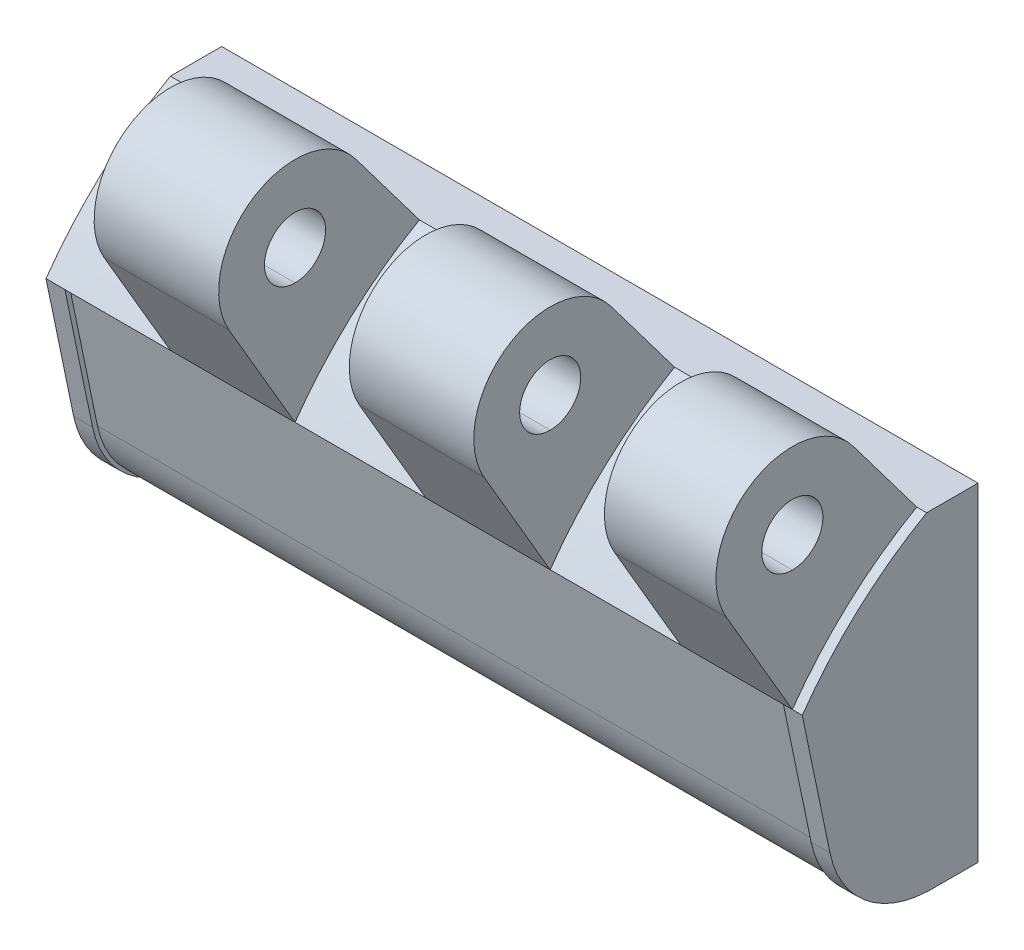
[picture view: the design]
ISO-10303-21;
HEADER;
FILE_DESCRIPTION(('STEP AP214'),'2;1');
FILE_NAME('part.step','',(''),(''),'','','');
FILE_SCHEMA(('AUTOMOTIVE_DESIGN { 1 0 10303 214 1 1 1 1 }'));
ENDSEC;
DATA;
#1=APPLICATION_CONTEXT('core data for automotive mechanical design processes');
#2=APPLICATION_PROTOCOL_DEFINITION('international standard','automotive_design',2000,#1);
#3=PRODUCT_CONTEXT('',#1,'mechanical');
#4=PRODUCT('Part','Part','',(#3));
#5=PRODUCT_RELATED_PRODUCT_CATEGORY('part','',(#4));
#6=PRODUCT_DEFINITION_FORMATION('','',#4);
#7=PRODUCT_DEFINITION_CONTEXT('part definition',#1,'design');
#8=PRODUCT_DEFINITION('design','',#6,#7);
#9=PRODUCT_DEFINITION_SHAPE('','',#8);
#10=(LENGTH_UNIT() NAMED_UNIT(*) SI_UNIT(.MILLI.,.METRE.));
#11=(NAMED_UNIT(*) PLANE_ANGLE_UNIT() SI_UNIT($,.RADIAN.));
#12=(NAMED_UNIT(*) SI_UNIT($,.STERADIAN.) SOLID_ANGLE_UNIT());
#13=UNCERTAINTY_MEASURE_WITH_UNIT(LENGTH_MEASURE(1.E-05),#10,'distance_accuracy_value','');
#14=(GEOMETRIC_REPRESENTATION_CONTEXT(3) GLOBAL_UNCERTAINTY_ASSIGNED_CONTEXT((#13)) GLOBAL_UNIT_ASSIGNED_CONTEXT((#10,
#11,#12)) REPRESENTATION_CONTEXT('',''));
#15=CARTESIAN_POINT('',(0.,0.,0.));
#16=DIRECTION('',(0.,0.,1.));
#17=DIRECTION('',(1.,0.,0.));
#18=AXIS2_PLACEMENT_3D('',#15,#16,#17);
#19=CARTESIAN_POINT('',(38.63875,-2.8772598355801,8.51410225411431));
#20=DIRECTION('',(0.,0.203476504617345,-0.979079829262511));
#21=DIRECTION('',(0.,-0.979079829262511,-0.203476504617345));
#22=AXIS2_PLACEMENT_3D('',#19,#20,#21);
#23=PLANE('',#22);
#24=DIRECTION('',(-1.,0.,0.));
#25=VECTOR('',#24,1.);
#26=CARTESIAN_POINT('',(-2.8867513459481,5.,10.151187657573));
#27=LINE('',#26,#25);
#28=CARTESIAN_POINT('',(-2.88675134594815,5.,10.151187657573));
#29=VERTEX_POINT('',#28);
#30=CARTESIAN_POINT('',(2.8867513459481,5.,10.151187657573));
#31=VERTEX_POINT('',#30);
#32=EDGE_CURVE('E546',#29,#31,#27,.F.);
#33=ORIENTED_EDGE('',*,*,#32,.T.);
#34=DIRECTION('',(0.492093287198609,-0.852330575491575,-0.177134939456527));
#35=VECTOR('',#34,1.);
#36=CARTESIAN_POINT('',(2.8867513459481,5.,10.151187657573));
#37=LINE('',#36,#35);
#38=CARTESIAN_POINT('',(5.77350269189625,0.,9.11206654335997));
#39=VERTEX_POINT('',#38);
#40=EDGE_CURVE('E565',#31,#39,#37,.T.);
#41=ORIENTED_EDGE('',*,*,#40,.T.);
#42=DIRECTION('',(-0.49209328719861,-0.852330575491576,-0.177134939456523));
#43=VECTOR('',#42,1.);
#44=CARTESIAN_POINT('',(5.77350269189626,0.,9.11206654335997));
#45=LINE('',#44,#43);
#46=CARTESIAN_POINT('',(4.1123159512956,-2.8772598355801,8.51410225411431));
#47=VERTEX_POINT('',#46);
#48=EDGE_CURVE('E578',#39,#47,#45,.T.);
#49=ORIENTED_EDGE('',*,*,#48,.T.);
#50=DIRECTION('',(1.,0.,0.));
#51=VECTOR('',#50,1.);
#52=CARTESIAN_POINT('',(38.63875,-2.8772598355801,8.51410225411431));
#53=LINE('',#52,#51);
#54=CARTESIAN_POINT('',(-4.11231595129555,-2.8772598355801,8.51410225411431));
#55=VERTEX_POINT('',#54);
#56=EDGE_CURVE('E447',#47,#55,#53,.F.);
#57=ORIENTED_EDGE('',*,*,#56,.T.);
#58=DIRECTION('',(-0.49209328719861,0.852330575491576,0.177134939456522));
#59=VECTOR('',#58,1.);
#60=CARTESIAN_POINT('',(-4.11231595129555,-2.8772598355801,8.51410225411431));
#61=LINE('',#60,#59);
#62=CARTESIAN_POINT('',(-5.77350269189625,0.,9.11206654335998));
#63=VERTEX_POINT('',#62);
#64=EDGE_CURVE('E536',#55,#63,#61,.T.);
#65=ORIENTED_EDGE('',*,*,#64,.T.);
#66=DIRECTION('',(0.492093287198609,0.852330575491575,0.177134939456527));
#67=VECTOR('',#66,1.);
#68=CARTESIAN_POINT('',(-5.7735026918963,0.,9.11206654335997));
#69=LINE('',#68,#67);
#70=EDGE_CURVE('E533',#63,#29,#69,.T.);
#71=ORIENTED_EDGE('',*,*,#70,.T.);
#72=EDGE_LOOP('',(#33,#41,#49,#57,#65,#71));
#73=FACE_BOUND('',#72,.T.);
#74=ADVANCED_FACE('F14',(#73),#23,.T.);
#75=CARTESIAN_POINT('',(38.63875,-1.75,3.09));
#76=DIRECTION('',(1.,0.,0.));
#77=DIRECTION('',(0.,1.,0.));
#78=AXIS2_PLACEMENT_3D('',#75,#76,#77);
#79=CYLINDRICAL_SURFACE('',#78,5.54);
#80=DIRECTION('',(1.,0.,0.));
#81=VECTOR('',#80,1.);
#82=CARTESIAN_POINT('',(2.8867513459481,-5.,7.57654655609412));
#83=LINE('',#82,#81);
#84=CARTESIAN_POINT('',(2.88675134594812,-5.,7.57654655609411));
#85=VERTEX_POINT('',#84);
#86=CARTESIAN_POINT('',(-2.8867513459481,-5.,7.57654655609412));
#87=VERTEX_POINT('',#86);
#88=EDGE_CURVE('E518',#85,#87,#83,.F.);
#89=ORIENTED_EDGE('',*,*,#88,.T.);
#90=CARTESIAN_POINT('',(-4.7631397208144,-1.75,3.09));
#91=DIRECTION('',(-0.866025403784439,-0.5,0.));
#92=DIRECTION('',(0.5,-0.866025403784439,0.));
#93=AXIS2_PLACEMENT_3D('',#90,#91,#92);
#94=ELLIPSE('',#93,6.39704098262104,5.54);
#95=EDGE_CURVE('E457',#87,#55,#94,.T.);
#96=ORIENTED_EDGE('',*,*,#95,.T.);
#97=ORIENTED_EDGE('',*,*,#56,.F.);
#98=CARTESIAN_POINT('',(4.7631397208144,-1.75,3.09));
#99=DIRECTION('',(0.866025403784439,-0.5,0.));
#100=DIRECTION('',(0.5,0.866025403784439,0.));
#101=AXIS2_PLACEMENT_3D('',#98,#99,#100);
#102=ELLIPSE('',#101,6.39704098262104,5.54);
#103=EDGE_CURVE('E520',#47,#85,#102,.T.);
#104=ORIENTED_EDGE('',*,*,#103,.T.);
#105=EDGE_LOOP('',(#89,#96,#97,#104));
#106=FACE_BOUND('',#105,.T.);
#107=ADVANCED_FACE('F836',(#106),#79,.F.);
#108=CARTESIAN_POINT('',(38.63875,-1.75,3.09));
#109=DIRECTION('',(1.,0.,0.));
#110=DIRECTION('',(0.,1.,0.));
#111=AXIS2_PLACEMENT_3D('',#108,#109,#110);
#112=CYLINDRICAL_SURFACE('',#111,5.54);
#113=DIRECTION('',(-1.,0.,0.));
#114=VECTOR('',#113,1.);
#115=CARTESIAN_POINT('',(38.63875,-2.8772598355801,8.51410225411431));
#116=LINE('',#115,#114);
#117=CARTESIAN_POINT('',(34.6123159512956,-2.8772598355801,8.51410225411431));
#118=VERTEX_POINT('',#117);
#119=CARTESIAN_POINT('',(26.3876840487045,-2.8772598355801,8.51410225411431));
#120=VERTEX_POINT('',#119);
#121=EDGE_CURVE('E444',#118,#120,#116,.T.);
#122=ORIENTED_EDGE('',*,*,#121,.F.);
#123=CARTESIAN_POINT('',(35.2631397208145,-1.75,3.09));
#124=DIRECTION('',(0.866025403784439,-0.5,0.));
#125=DIRECTION('',(0.5,0.866025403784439,0.));
#126=AXIS2_PLACEMENT_3D('',#123,#124,#125);
#127=ELLIPSE('',#126,6.39704098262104,5.54);
#128=CARTESIAN_POINT('',(33.3867513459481,-5.,7.57654655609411));
#129=VERTEX_POINT('',#128);
#130=EDGE_CURVE('E456',#118,#129,#127,.T.);
#131=ORIENTED_EDGE('',*,*,#130,.T.);
#132=DIRECTION('',(1.,0.,0.));
#133=VECTOR('',#132,1.);
#134=CARTESIAN_POINT('',(33.3867513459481,-5.,7.57654655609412));
#135=LINE('',#134,#133);
#136=CARTESIAN_POINT('',(27.6132486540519,-5.,7.57654655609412));
#137=VERTEX_POINT('',#136);
#138=EDGE_CURVE('E454',#129,#137,#135,.F.);
#139=ORIENTED_EDGE('',*,*,#138,.T.);
#140=CARTESIAN_POINT('',(25.7368602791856,-1.75,3.09));
#141=DIRECTION('',(-0.866025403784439,-0.5,0.));
#142=DIRECTION('',(0.5,-0.866025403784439,0.));
#143=AXIS2_PLACEMENT_3D('',#140,#141,#142);
#144=ELLIPSE('',#143,6.39704098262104,5.54);
#145=EDGE_CURVE('E737',#137,#120,#144,.T.);
#146=ORIENTED_EDGE('',*,*,#145,.T.);
#147=EDGE_LOOP('',(#122,#131,#139,#146));
#148=FACE_BOUND('',#147,.T.);
#149=ADVANCED_FACE('F1040',(#148),#112,.F.);
#150=CARTESIAN_POINT('',(38.63875,-2.8772598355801,8.51410225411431));
#151=DIRECTION('',(0.,0.203476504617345,-0.979079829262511));
#152=DIRECTION('',(0.,-0.979079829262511,-0.203476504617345));
#153=AXIS2_PLACEMENT_3D('',#150,#151,#152);
#154=PLANE('',#153);
#155=DIRECTION('',(-0.49209328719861,-0.852330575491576,-0.177134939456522));
#156=VECTOR('',#155,1.);
#157=CARTESIAN_POINT('',(36.2735026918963,0.,9.11206654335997));
#158=LINE('',#157,#156);
#159=CARTESIAN_POINT('',(36.2735026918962,0.,9.11206654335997));
#160=VERTEX_POINT('',#159);
#161=EDGE_CURVE('E510',#160,#118,#158,.T.);
#162=ORIENTED_EDGE('',*,*,#161,.T.);
#163=ORIENTED_EDGE('',*,*,#121,.T.);
#164=DIRECTION('',(-0.49209328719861,0.852330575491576,0.177134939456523));
#165=VECTOR('',#164,1.);
#166=CARTESIAN_POINT('',(26.3876840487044,-2.8772598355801,8.51410225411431));
#167=LINE('',#166,#165);
#168=CARTESIAN_POINT('',(24.7264973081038,0.,9.11206654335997));
#169=VERTEX_POINT('',#168);
#170=EDGE_CURVE('E739',#120,#169,#167,.T.);
#171=ORIENTED_EDGE('',*,*,#170,.T.);
#172=DIRECTION('',(0.492093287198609,0.852330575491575,0.177134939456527));
#173=VECTOR('',#172,1.);
#174=CARTESIAN_POINT('',(24.7264973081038,0.,9.11206654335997));
#175=LINE('',#174,#173);
#176=CARTESIAN_POINT('',(27.6132486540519,5.,10.151187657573));
#177=VERTEX_POINT('',#176);
#178=EDGE_CURVE('E451',#169,#177,#175,.T.);
#179=ORIENTED_EDGE('',*,*,#178,.T.);
#180=DIRECTION('',(-1.,0.,0.));
#181=VECTOR('',#180,1.);
#182=CARTESIAN_POINT('',(27.6132486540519,5.,10.151187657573));
#183=LINE('',#182,#181);
#184=CARTESIAN_POINT('',(33.3867513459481,5.,10.151187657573));
#185=VERTEX_POINT('',#184);
#186=EDGE_CURVE('E483',#177,#185,#183,.F.);
#187=ORIENTED_EDGE('',*,*,#186,.T.);
#188=DIRECTION('',(0.492093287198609,-0.852330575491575,-0.177134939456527));
#189=VECTOR('',#188,1.);
#190=CARTESIAN_POINT('',(33.3867513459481,5.,10.151187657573));
#191=LINE('',#190,#189);
#192=EDGE_CURVE('E497',#185,#160,#191,.T.);
#193=ORIENTED_EDGE('',*,*,#192,.T.);
#194=EDGE_LOOP('',(#162,#163,#171,#179,#187,#193));
#195=FACE_BOUND('',#194,.T.);
#196=ADVANCED_FACE('F1042',(#195),#154,.T.);
#197=CARTESIAN_POINT('',(38.7625,-1.75,3.09));
#198=DIRECTION('',(1.,0.,0.));
#199=DIRECTION('',(0.,1.,0.));
#200=AXIS2_PLACEMENT_3D('',#197,#198,#199);
#201=CYLINDRICAL_SURFACE('',#200,5.54);
#202=CARTESIAN_POINT('',(-8.2625,-1.75,3.09));
#203=DIRECTION('',(1.,0.,0.));
#204=DIRECTION('',(0.,1.,0.));
#205=AXIS2_PLACEMENT_3D('',#202,#203,#204);
#206=CIRCLE('',#205,5.54);
#207=CARTESIAN_POINT('',(-8.2625,-7.2834549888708,3.35921345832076));
#208=VERTEX_POINT('',#207);
#209=CARTESIAN_POINT('',(-8.2625,-2.8772598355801,8.51410225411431));
#210=VERTEX_POINT('',#209);
#211=EDGE_CURVE('E734',#208,#210,#206,.F.);
#212=ORIENTED_EDGE('',*,*,#211,.F.);
#213=DIRECTION('',(1.,0.,0.));
#214=VECTOR('',#213,1.);
#215=CARTESIAN_POINT('',(38.7625,-7.2834549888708,3.35921345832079));
#216=LINE('',#215,#214);
#217=CARTESIAN_POINT('',(-8.13875,-7.2834549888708,3.35921345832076));
#218=VERTEX_POINT('',#217);
#219=EDGE_CURVE('E375',#208,#218,#216,.T.);
#220=ORIENTED_EDGE('',*,*,#219,.T.);
#221=CARTESIAN_POINT('',(-8.13875,-1.75,3.09));
#222=DIRECTION('',(1.,0.,0.));
#223=DIRECTION('',(0.,1.,0.));
#224=AXIS2_PLACEMENT_3D('',#221,#222,#223);
#225=CIRCLE('',#224,5.54);
#226=CARTESIAN_POINT('',(-8.13875,-2.8772598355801,8.51410225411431));
#227=VERTEX_POINT('',#226);
#228=EDGE_CURVE('E17',#218,#227,#225,.F.);
#229=ORIENTED_EDGE('',*,*,#228,.T.);
#230=DIRECTION('',(-1.,0.,0.));
#231=VECTOR('',#230,1.);
#232=CARTESIAN_POINT('',(38.7625,-2.8772598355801,8.51410225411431));
#233=LINE('',#232,#231);
#234=EDGE_CURVE('E363',#227,#210,#233,.T.);
#235=ORIENTED_EDGE('',*,*,#234,.T.);
#236=EDGE_LOOP('',(#212,#220,#229,#235));
#237=FACE_BOUND('',#236,.T.);
#238=ADVANCED_FACE('F378',(#237),#201,.T.);
#239=CARTESIAN_POINT('',(38.7625,-2.8772598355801,8.51410225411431));
#240=DIRECTION('',(0.,0.203476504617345,-0.979079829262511));
#241=DIRECTION('',(0.,-0.979079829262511,-0.203476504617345));
#242=AXIS2_PLACEMENT_3D('',#239,#240,#241);
#243=PLANE('',#242);
#244=DIRECTION('',(-1.,0.,0.));
#245=VECTOR('',#244,1.);
#246=CARTESIAN_POINT('',(38.7625,5.5926726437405,10.2743593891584));
#247=LINE('',#246,#245);
#248=CARTESIAN_POINT('',(-8.2625,5.5926726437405,10.2743593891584));
#249=VERTEX_POINT('',#248);
#250=CARTESIAN_POINT('',(-8.13875,5.5926726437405,10.2743593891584));
#251=VERTEX_POINT('',#250);
#252=EDGE_CURVE('E374',#249,#251,#247,.F.);
#253=ORIENTED_EDGE('',*,*,#252,.F.);
#254=DIRECTION('',(0.,0.979079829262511,0.203476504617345));
#255=VECTOR('',#254,1.);
#256=CARTESIAN_POINT('',(-8.2625,-2.8772598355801,8.51410225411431));
#257=LINE('',#256,#255);
#258=EDGE_CURVE('E370',#210,#249,#257,.T.);
#259=ORIENTED_EDGE('',*,*,#258,.F.);
#260=ORIENTED_EDGE('',*,*,#234,.F.);
#261=DIRECTION('',(0.,0.979079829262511,0.203476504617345));
#262=VECTOR('',#261,1.);
#263=CARTESIAN_POINT('',(-8.13875,-2.8772598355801,8.51410225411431));
#264=LINE('',#263,#262);
#265=EDGE_CURVE('E367',#227,#251,#264,.T.);
#266=ORIENTED_EDGE('',*,*,#265,.T.);
#267=EDGE_LOOP('',(#253,#259,#260,#266));
#268=FACE_BOUND('',#267,.T.);
#269=ADVANCED_FACE('F365',(#268),#243,.F.);
#270=CARTESIAN_POINT('',(6.8,15.5,11.5));
#271=DIRECTION('',(1.,0.,0.));
#272=DIRECTION('',(0.,1.,0.));
#273=AXIS2_PLACEMENT_3D('',#270,#271,#272);
#274=CYLINDRICAL_SURFACE('',#273,2.);
#275=CARTESIAN_POINT('',(6.8,15.5,11.5));
#276=DIRECTION('',(1.,0.,0.));
#277=DIRECTION('',(0.,1.,0.));
#278=AXIS2_PLACEMENT_3D('',#275,#276,#277);
#279=CIRCLE('',#278,2.);
#280=CARTESIAN_POINT('',(6.8,13.5,11.5));
#281=VERTEX_POINT('',#280);
#282=CARTESIAN_POINT('',(6.8,17.5,11.5));
#283=VERTEX_POINT('',#282);
#284=EDGE_CURVE('E720',#281,#283,#279,.F.);
#285=ORIENTED_EDGE('',*,*,#284,.F.);
#286=DIRECTION('',(1.,0.,0.));
#287=VECTOR('',#286,1.);
#288=CARTESIAN_POINT('',(6.8,13.5,11.5));
#289=LINE('',#288,#287);
#290=CARTESIAN_POINT('',(-1.35,13.5,11.5));
#291=VERTEX_POINT('',#290);
#292=EDGE_CURVE('E434',#281,#291,#289,.F.);
#293=ORIENTED_EDGE('',*,*,#292,.T.);
#294=CARTESIAN_POINT('',(-1.35,15.5,11.5));
#295=DIRECTION('',(1.,0.,0.));
#296=DIRECTION('',(0.,1.,0.));
#297=AXIS2_PLACEMENT_3D('',#294,#295,#296);
#298=CIRCLE('',#297,2.);
#299=CARTESIAN_POINT('',(-1.35,17.5,11.5));
#300=VERTEX_POINT('',#299);
#301=EDGE_CURVE('E732',#291,#300,#298,.F.);
#302=ORIENTED_EDGE('',*,*,#301,.T.);
#303=DIRECTION('',(1.,0.,0.));
#304=VECTOR('',#303,1.);
#305=CARTESIAN_POINT('',(6.8,17.5,11.5));
#306=LINE('',#305,#304);
#307=EDGE_CURVE('E432',#300,#283,#306,.T.);
#308=ORIENTED_EDGE('',*,*,#307,.T.);
#309=EDGE_LOOP('',(#285,#293,#302,#308));
#310=FACE_BOUND('',#309,.T.);
#311=ADVANCED_FACE('F1081',(#310),#274,.F.);
#312=CARTESIAN_POINT('',(6.8,15.5,11.5));
#313=DIRECTION('',(1.,0.,0.));
#314=DIRECTION('',(0.,1.,0.));
#315=AXIS2_PLACEMENT_3D('',#312,#313,#314);
#316=CYLINDRICAL_SURFACE('',#315,2.);
#317=CARTESIAN_POINT('',(-1.35,15.5,11.5));
#318=DIRECTION('',(1.,0.,0.));
#319=DIRECTION('',(0.,1.,0.));
#320=AXIS2_PLACEMENT_3D('',#317,#318,#319);
#321=CIRCLE('',#320,2.);
#322=EDGE_CURVE('E729',#300,#291,#321,.F.);
#323=ORIENTED_EDGE('',*,*,#322,.T.);
#324=ORIENTED_EDGE('',*,*,#292,.F.);
#325=CARTESIAN_POINT('',(6.8,15.5,11.5));
#326=DIRECTION('',(1.,0.,0.));
#327=DIRECTION('',(0.,1.,0.));
#328=AXIS2_PLACEMENT_3D('',#325,#326,#327);
#329=CIRCLE('',#328,2.);
#330=EDGE_CURVE('E717',#283,#281,#329,.F.);
#331=ORIENTED_EDGE('',*,*,#330,.F.);
#332=ORIENTED_EDGE('',*,*,#307,.F.);
#333=EDGE_LOOP('',(#323,#324,#331,#332));
#334=FACE_BOUND('',#333,.T.);
#335=ADVANCED_FACE('F1090',(#334),#316,.F.);
#336=CARTESIAN_POINT('',(15.35,15.5,11.5));
#337=DIRECTION('',(-1.,0.,0.));
#338=DIRECTION('',(0.,-1.,0.));
#339=AXIS2_PLACEMENT_3D('',#336,#337,#338);
#340=CYLINDRICAL_SURFACE('',#339,2.);
#341=CARTESIAN_POINT('',(23.5,15.5,11.5));
#342=DIRECTION('',(-1.,0.,0.));
#343=DIRECTION('',(0.,-1.,0.));
#344=AXIS2_PLACEMENT_3D('',#341,#342,#343);
#345=CIRCLE('',#344,2.);
#346=CARTESIAN_POINT('',(23.5,13.5,11.5));
#347=VERTEX_POINT('',#346);
#348=CARTESIAN_POINT('',(23.5,17.5,11.5));
#349=VERTEX_POINT('',#348);
#350=EDGE_CURVE('E427',#347,#349,#345,.T.);
#351=ORIENTED_EDGE('',*,*,#350,.F.);
#352=DIRECTION('',(-1.,0.,0.));
#353=VECTOR('',#352,1.);
#354=CARTESIAN_POINT('',(15.35,13.5,11.5));
#355=LINE('',#354,#353);
#356=CARTESIAN_POINT('',(15.35,13.5,11.5));
#357=VERTEX_POINT('',#356);
#358=EDGE_CURVE('E430',#347,#357,#355,.T.);
#359=ORIENTED_EDGE('',*,*,#358,.T.);
#360=CARTESIAN_POINT('',(15.35,15.5,11.5));
#361=DIRECTION('',(-1.,0.,0.));
#362=DIRECTION('',(0.,-1.,0.));
#363=AXIS2_PLACEMENT_3D('',#360,#361,#362);
#364=CIRCLE('',#363,2.);
#365=CARTESIAN_POINT('',(15.35,17.5,11.5));
#366=VERTEX_POINT('',#365);
#367=EDGE_CURVE('E710',#357,#366,#364,.T.);
#368=ORIENTED_EDGE('',*,*,#367,.T.);
#369=DIRECTION('',(-1.,0.,0.));
#370=VECTOR('',#369,1.);
#371=CARTESIAN_POINT('',(15.35,17.5,11.5));
#372=LINE('',#371,#370);
#373=EDGE_CURVE('E420',#366,#349,#372,.F.);
#374=ORIENTED_EDGE('',*,*,#373,.T.);
#375=EDGE_LOOP('',(#351,#359,#368,#374));
#376=FACE_BOUND('',#375,.T.);
#377=ADVANCED_FACE('F1100',(#376),#340,.F.);
#378=CARTESIAN_POINT('',(15.35,15.5,11.5));
#379=DIRECTION('',(-1.,0.,0.));
#380=DIRECTION('',(0.,-1.,0.));
#381=AXIS2_PLACEMENT_3D('',#378,#379,#380);
#382=CYLINDRICAL_SURFACE('',#381,2.);
#383=CARTESIAN_POINT('',(15.35,15.5,11.5));
#384=DIRECTION('',(-1.,0.,0.));
#385=DIRECTION('',(0.,-1.,0.));
#386=AXIS2_PLACEMENT_3D('',#383,#384,#385);
#387=CIRCLE('',#386,2.);
#388=EDGE_CURVE('E713',#366,#357,#387,.T.);
#389=ORIENTED_EDGE('',*,*,#388,.T.);
#390=ORIENTED_EDGE('',*,*,#358,.F.);
#391=CARTESIAN_POINT('',(23.5,15.5,11.5));
#392=DIRECTION('',(-1.,0.,0.));
#393=DIRECTION('',(0.,-1.,0.));
#394=AXIS2_PLACEMENT_3D('',#391,#392,#393);
#395=CIRCLE('',#394,2.);
#396=EDGE_CURVE('E703',#349,#347,#395,.T.);
#397=ORIENTED_EDGE('',*,*,#396,.F.);
#398=ORIENTED_EDGE('',*,*,#373,.F.);
#399=EDGE_LOOP('',(#389,#390,#397,#398));
#400=FACE_BOUND('',#399,.T.);
#401=ADVANCED_FACE('F1110',(#400),#382,.F.);
#402=CARTESIAN_POINT('',(6.8,12.9766151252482,15.8165412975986));
#403=DIRECTION('',(0.,-0.504676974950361,0.863308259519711));
#404=DIRECTION('',(0.,0.863308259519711,0.504676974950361));
#405=AXIS2_PLACEMENT_3D('',#402,#403,#404);
#406=PLANE('',#405);
#407=DIRECTION('',(0.,-0.863308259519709,-0.504676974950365));
#408=VECTOR('',#407,1.);
#409=CARTESIAN_POINT('',(6.8,12.9766151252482,15.8165412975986));
#410=LINE('',#409,#408);
#411=CARTESIAN_POINT('',(6.8,12.9766151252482,15.8165412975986));
#412=VERTEX_POINT('',#411);
#413=CARTESIAN_POINT('',(6.8,5.59267264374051,11.5));
#414=VERTEX_POINT('',#413);
#415=EDGE_CURVE('E723',#412,#414,#410,.T.);
#416=ORIENTED_EDGE('',*,*,#415,.F.);
#417=DIRECTION('',(1.,0.,0.));
#418=VECTOR('',#417,1.);
#419=CARTESIAN_POINT('',(6.8,12.9766151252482,15.8165412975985));
#420=LINE('',#419,#418);
#421=CARTESIAN_POINT('',(-1.35,12.9766151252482,15.8165412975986));
#422=VERTEX_POINT('',#421);
#423=EDGE_CURVE('E436',#422,#412,#420,.T.);
#424=ORIENTED_EDGE('',*,*,#423,.F.);
#425=DIRECTION('',(0.,-0.863308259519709,-0.504676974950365));
#426=VECTOR('',#425,1.);
#427=CARTESIAN_POINT('',(-1.35,12.9766151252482,15.8165412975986));
#428=LINE('',#427,#426);
#429=CARTESIAN_POINT('',(-1.35,5.59267264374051,11.5));
#430=VERTEX_POINT('',#429);
#431=EDGE_CURVE('E728',#422,#430,#428,.T.);
#432=ORIENTED_EDGE('',*,*,#431,.T.);
#433=DIRECTION('',(-1.,0.,0.));
#434=VECTOR('',#433,1.);
#435=CARTESIAN_POINT('',(38.7625,5.5926726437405,11.5));
#436=LINE('',#435,#434);
#437=EDGE_CURVE('E1550',#430,#414,#436,.F.);
#438=ORIENTED_EDGE('',*,*,#437,.T.);
#439=EDGE_LOOP('',(#416,#424,#432,#438));
#440=FACE_BOUND('',#439,.T.);
#441=ADVANCED_FACE('F1120',(#440),#406,.T.);
#442=CARTESIAN_POINT('',(15.35,5.5926726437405,11.5));
#443=DIRECTION('',(0.,-0.504676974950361,0.863308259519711));
#444=DIRECTION('',(0.,0.863308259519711,0.504676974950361));
#445=AXIS2_PLACEMENT_3D('',#442,#443,#444);
#446=PLANE('',#445);
#447=DIRECTION('',(0.,-0.863308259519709,-0.504676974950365));
#448=VECTOR('',#447,1.);
#449=CARTESIAN_POINT('',(15.35,12.9766151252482,15.8165412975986));
#450=LINE('',#449,#448);
#451=CARTESIAN_POINT('',(15.35,12.9766151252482,15.8165412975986));
#452=VERTEX_POINT('',#451);
#453=CARTESIAN_POINT('',(15.35,5.59267264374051,11.5));
#454=VERTEX_POINT('',#453);
#455=EDGE_CURVE('E716',#452,#454,#450,.T.);
#456=ORIENTED_EDGE('',*,*,#455,.T.);
#457=DIRECTION('',(-1.,0.,0.));
#458=VECTOR('',#457,1.);
#459=CARTESIAN_POINT('',(38.7625,5.5926726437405,11.5));
#460=LINE('',#459,#458);
#461=CARTESIAN_POINT('',(23.5,5.59267264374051,11.5));
#462=VERTEX_POINT('',#461);
#463=EDGE_CURVE('E1548',#454,#462,#460,.F.);
#464=ORIENTED_EDGE('',*,*,#463,.T.);
#465=DIRECTION('',(0.,-0.863308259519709,-0.504676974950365));
#466=VECTOR('',#465,1.);
#467=CARTESIAN_POINT('',(23.5,12.9766151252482,15.8165412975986));
#468=LINE('',#467,#466);
#469=CARTESIAN_POINT('',(23.5,12.9766151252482,15.8165412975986));
#470=VERTEX_POINT('',#469);
#471=EDGE_CURVE('E702',#470,#462,#468,.T.);
#472=ORIENTED_EDGE('',*,*,#471,.F.);
#473=DIRECTION('',(-1.,0.,0.));
#474=VECTOR('',#473,1.);
#475=CARTESIAN_POINT('',(15.35,12.9766151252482,15.8165412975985));
#476=LINE('',#475,#474);
#477=EDGE_CURVE('E425',#452,#470,#476,.F.);
#478=ORIENTED_EDGE('',*,*,#477,.F.);
#479=EDGE_LOOP('',(#456,#464,#472,#478));
#480=FACE_BOUND('',#479,.T.);
#481=ADVANCED_FACE('F1130',(#480),#446,.T.);
#482=CARTESIAN_POINT('',(32.05,15.5,11.5));
#483=DIRECTION('',(-1.,0.,0.));
#484=DIRECTION('',(0.,-1.,0.));
#485=AXIS2_PLACEMENT_3D('',#482,#483,#484);
#486=CYLINDRICAL_SURFACE('',#485,2.);
#487=CARTESIAN_POINT('',(39.35,15.5,11.5));
#488=DIRECTION('',(-1.,0.,0.));
#489=DIRECTION('',(0.,-1.,0.));
#490=AXIS2_PLACEMENT_3D('',#487,#488,#489);
#491=CIRCLE('',#490,2.);
#492=CARTESIAN_POINT('',(39.35,13.5,11.5));
#493=VERTEX_POINT('',#492);
#494=CARTESIAN_POINT('',(39.35,17.5,11.5));
#495=VERTEX_POINT('',#494);
#496=EDGE_CURVE('E415',#493,#495,#491,.T.);
#497=ORIENTED_EDGE('',*,*,#496,.F.);
#498=DIRECTION('',(-1.,0.,0.));
#499=VECTOR('',#498,1.);
#500=CARTESIAN_POINT('',(32.05,13.5,11.5));
#501=LINE('',#500,#499);
#502=CARTESIAN_POINT('',(32.05,13.5,11.5));
#503=VERTEX_POINT('',#502);
#504=EDGE_CURVE('E418',#493,#503,#501,.T.);
#505=ORIENTED_EDGE('',*,*,#504,.T.);
#506=CARTESIAN_POINT('',(32.05,15.5,11.5));
#507=DIRECTION('',(-1.,0.,0.));
#508=DIRECTION('',(0.,-1.,0.));
#509=AXIS2_PLACEMENT_3D('',#506,#507,#508);
#510=CIRCLE('',#509,2.);
#511=CARTESIAN_POINT('',(32.05,17.5,11.5));
#512=VERTEX_POINT('',#511);
#513=EDGE_CURVE('E693',#503,#512,#510,.T.);
#514=ORIENTED_EDGE('',*,*,#513,.T.);
#515=DIRECTION('',(-1.,0.,0.));
#516=VECTOR('',#515,1.);
#517=CARTESIAN_POINT('',(32.05,17.5,11.5));
#518=LINE('',#517,#516);
#519=EDGE_CURVE('E410',#512,#495,#518,.F.);
#520=ORIENTED_EDGE('',*,*,#519,.T.);
#521=EDGE_LOOP('',(#497,#505,#514,#520));
#522=FACE_BOUND('',#521,.T.);
#523=ADVANCED_FACE('F1140',(#522),#486,.F.);
#524=CARTESIAN_POINT('',(32.05,15.5,11.5));
#525=DIRECTION('',(-1.,0.,0.));
#526=DIRECTION('',(0.,-1.,0.));
#527=AXIS2_PLACEMENT_3D('',#524,#525,#526);
#528=CYLINDRICAL_SURFACE('',#527,2.);
#529=CARTESIAN_POINT('',(32.05,15.5,11.5));
#530=DIRECTION('',(-1.,0.,0.));
#531=DIRECTION('',(0.,-1.,0.));
#532=AXIS2_PLACEMENT_3D('',#529,#530,#531);
#533=CIRCLE('',#532,2.);
#534=EDGE_CURVE('E696',#512,#503,#533,.T.);
#535=ORIENTED_EDGE('',*,*,#534,.T.);
#536=ORIENTED_EDGE('',*,*,#504,.F.);
#537=CARTESIAN_POINT('',(39.35,15.5,11.5));
#538=DIRECTION('',(-1.,0.,0.));
#539=DIRECTION('',(0.,-1.,0.));
#540=AXIS2_PLACEMENT_3D('',#537,#538,#539);
#541=CIRCLE('',#540,2.);
#542=EDGE_CURVE('E686',#495,#493,#541,.T.);
#543=ORIENTED_EDGE('',*,*,#542,.F.);
#544=ORIENTED_EDGE('',*,*,#519,.F.);
#545=EDGE_LOOP('',(#535,#536,#543,#544));
#546=FACE_BOUND('',#545,.T.);
#547=ADVANCED_FACE('F1150',(#546),#528,.F.);
#548=CARTESIAN_POINT('',(32.05,5.5926726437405,11.5));
#549=DIRECTION('',(0.,-0.504676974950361,0.863308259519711));
#550=DIRECTION('',(0.,0.863308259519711,0.504676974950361));
#551=AXIS2_PLACEMENT_3D('',#548,#549,#550);
#552=PLANE('',#551);
#553=DIRECTION('',(-1.,0.,0.));
#554=VECTOR('',#553,1.);
#555=CARTESIAN_POINT('',(38.7625,5.5926726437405,11.5));
#556=LINE('',#555,#554);
#557=CARTESIAN_POINT('',(32.05,5.59267264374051,11.5));
#558=VERTEX_POINT('',#557);
#559=CARTESIAN_POINT('',(38.7625,5.5926726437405,11.5));
#560=VERTEX_POINT('',#559);
#561=EDGE_CURVE('E403',#558,#560,#556,.F.);
#562=ORIENTED_EDGE('',*,*,#561,.T.);
#563=DIRECTION('',(-1.,0.,0.));
#564=VECTOR('',#563,1.);
#565=CARTESIAN_POINT('',(32.05,5.5926726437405,11.5));
#566=LINE('',#565,#564);
#567=CARTESIAN_POINT('',(39.35,5.59267264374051,11.5));
#568=VERTEX_POINT('',#567);
#569=EDGE_CURVE('E408',#560,#568,#566,.F.);
#570=ORIENTED_EDGE('',*,*,#569,.T.);
#571=DIRECTION('',(0.,-0.863308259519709,-0.504676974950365));
#572=VECTOR('',#571,1.);
#573=CARTESIAN_POINT('',(39.35,12.9766151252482,15.8165412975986));
#574=LINE('',#573,#572);
#575=CARTESIAN_POINT('',(39.35,12.9766151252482,15.8165412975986));
#576=VERTEX_POINT('',#575);
#577=EDGE_CURVE('E685',#576,#568,#574,.T.);
#578=ORIENTED_EDGE('',*,*,#577,.F.);
#579=DIRECTION('',(-1.,0.,0.));
#580=VECTOR('',#579,1.);
#581=CARTESIAN_POINT('',(32.05,12.9766151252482,15.8165412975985));
#582=LINE('',#581,#580);
#583=CARTESIAN_POINT('',(32.05,12.9766151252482,15.8165412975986));
#584=VERTEX_POINT('',#583);
#585=EDGE_CURVE('E413',#584,#576,#582,.F.);
#586=ORIENTED_EDGE('',*,*,#585,.F.);
#587=DIRECTION('',(0.,-0.863308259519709,-0.504676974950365));
#588=VECTOR('',#587,1.);
#589=CARTESIAN_POINT('',(32.05,12.9766151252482,15.8165412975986));
#590=LINE('',#589,#588);
#591=EDGE_CURVE('E590',#584,#558,#590,.T.);
#592=ORIENTED_EDGE('',*,*,#591,.T.);
#593=EDGE_LOOP('',(#562,#570,#578,#586,#592));
#594=FACE_BOUND('',#593,.T.);
#595=ADVANCED_FACE('F1160',(#594),#552,.T.);
#596=CARTESIAN_POINT('',(38.7625,-1.75,3.09));
#597=DIRECTION('',(1.,0.,0.));
#598=DIRECTION('',(0.,1.,0.));
#599=AXIS2_PLACEMENT_3D('',#596,#597,#598);
#600=CYLINDRICAL_SURFACE('',#599,5.54);
#601=CARTESIAN_POINT('',(38.7625,-1.75,3.09));
#602=DIRECTION('',(1.,0.,0.));
#603=DIRECTION('',(0.,1.,0.));
#604=AXIS2_PLACEMENT_3D('',#601,#602,#603);
#605=CIRCLE('',#604,5.54);
#606=CARTESIAN_POINT('',(38.7625,-7.2834549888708,3.35921345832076));
#607=VERTEX_POINT('',#606);
#608=CARTESIAN_POINT('',(38.7625,-2.8772598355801,8.51410225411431));
#609=VERTEX_POINT('',#608);
#610=EDGE_CURVE('E678',#607,#609,#605,.F.);
#611=ORIENTED_EDGE('',*,*,#610,.T.);
#612=DIRECTION('',(-1.,0.,0.));
#613=VECTOR('',#612,1.);
#614=CARTESIAN_POINT('',(38.7625,-2.8772598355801,8.51410225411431));
#615=LINE('',#614,#613);
#616=CARTESIAN_POINT('',(38.63875,-2.8772598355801,8.51410225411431));
#617=VERTEX_POINT('',#616);
#618=EDGE_CURVE('E384',#609,#617,#615,.T.);
#619=ORIENTED_EDGE('',*,*,#618,.T.);
#620=CARTESIAN_POINT('',(38.63875,-1.75,3.09));
#621=DIRECTION('',(1.,0.,0.));
#622=DIRECTION('',(0.,1.,0.));
#623=AXIS2_PLACEMENT_3D('',#620,#621,#622);
#624=CIRCLE('',#623,5.54);
#625=CARTESIAN_POINT('',(38.63875,-7.2834549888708,3.35921345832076));
#626=VERTEX_POINT('',#625);
#627=EDGE_CURVE('E745',#626,#617,#624,.F.);
#628=ORIENTED_EDGE('',*,*,#627,.F.);
#629=DIRECTION('',(1.,0.,0.));
#630=VECTOR('',#629,1.);
#631=CARTESIAN_POINT('',(38.7625,-7.2834549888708,3.35921345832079));
#632=LINE('',#631,#630);
#633=EDGE_CURVE('E387',#626,#607,#632,.T.);
#634=ORIENTED_EDGE('',*,*,#633,.T.);
#635=EDGE_LOOP('',(#611,#619,#628,#634));
#636=FACE_BOUND('',#635,.T.);
#637=ADVANCED_FACE('F1170',(#636),#600,.T.);
#638=CARTESIAN_POINT('',(38.7625,-2.8772598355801,8.51410225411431));
#639=DIRECTION('',(0.,0.203476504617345,-0.979079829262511));
#640=DIRECTION('',(0.,-0.979079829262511,-0.203476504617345));
#641=AXIS2_PLACEMENT_3D('',#638,#639,#640);
#642=PLANE('',#641);
#643=ORIENTED_EDGE('',*,*,#618,.F.);
#644=DIRECTION('',(0.,0.979079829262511,0.203476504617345));
#645=VECTOR('',#644,1.);
#646=CARTESIAN_POINT('',(38.7625,-2.8772598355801,8.51410225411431));
#647=LINE('',#646,#645);
#648=CARTESIAN_POINT('',(38.7625,5.5926726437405,10.2743593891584));
#649=VERTEX_POINT('',#648);
#650=EDGE_CURVE('E680',#609,#649,#647,.T.);
#651=ORIENTED_EDGE('',*,*,#650,.T.);
#652=DIRECTION('',(-1.,0.,0.));
#653=VECTOR('',#652,1.);
#654=CARTESIAN_POINT('',(38.7625,5.5926726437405,10.2743593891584));
#655=LINE('',#654,#653);
#656=CARTESIAN_POINT('',(38.63875,5.5926726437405,10.2743593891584));
#657=VERTEX_POINT('',#656);
#658=EDGE_CURVE('E400',#649,#657,#655,.T.);
#659=ORIENTED_EDGE('',*,*,#658,.T.);
#660=DIRECTION('',(0.,0.979079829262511,0.203476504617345));
#661=VECTOR('',#660,1.);
#662=CARTESIAN_POINT('',(38.63875,-2.8772598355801,8.51410225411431));
#663=LINE('',#662,#661);
#664=EDGE_CURVE('E397',#617,#657,#663,.T.);
#665=ORIENTED_EDGE('',*,*,#664,.F.);
#666=EDGE_LOOP('',(#643,#651,#659,#665));
#667=FACE_BOUND('',#666,.T.);
#668=ADVANCED_FACE('F1180',(#667),#642,.F.);
#669=CARTESIAN_POINT('',(-8.13875,15.5,0.));
#670=DIRECTION('',(1.,0.,0.));
#671=DIRECTION('',(0.,1.,0.));
#672=AXIS2_PLACEMENT_3D('',#669,#670,#671);
#673=PLANE('',#672);
#674=DIRECTION('',(0.,1.,0.));
#675=VECTOR('',#674,1.);
#676=CARTESIAN_POINT('',(-8.13875,15.5,3.35921345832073));
#677=LINE('',#676,#675);
#678=CARTESIAN_POINT('',(-8.13875,-8.2844566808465,3.35921345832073));
#679=VERTEX_POINT('',#678);
#680=EDGE_CURVE('E357',#679,#218,#677,.T.);
#681=ORIENTED_EDGE('',*,*,#680,.F.);
#682=CARTESIAN_POINT('',(-8.13875,-1.75,3.09));
#683=DIRECTION('',(1.,0.,0.));
#684=DIRECTION('',(0.,1.,0.));
#685=AXIS2_PLACEMENT_3D('',#682,#683,#684);
#686=CIRCLE('',#685,6.54);
#687=CARTESIAN_POINT('',(-8.13875,-3.0807363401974,9.49318208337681));
#688=VERTEX_POINT('',#687);
#689=EDGE_CURVE('E674',#688,#679,#686,.T.);
#690=ORIENTED_EDGE('',*,*,#689,.F.);
#691=DIRECTION('',(0.,0.979079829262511,0.203476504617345));
#692=VECTOR('',#691,1.);
#693=CARTESIAN_POINT('',(-8.13875,5.5926726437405,11.2957265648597));
#694=LINE('',#693,#692);
#695=CARTESIAN_POINT('',(-8.13875,5.5926726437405,11.2957265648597));
#696=VERTEX_POINT('',#695);
#697=EDGE_CURVE('E393',#696,#688,#694,.F.);
#698=ORIENTED_EDGE('',*,*,#697,.F.);
#699=DIRECTION('',(0.,0.,1.));
#700=VECTOR('',#699,1.);
#701=CARTESIAN_POINT('',(-8.13875,5.5926726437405,10.2743593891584));
#702=LINE('',#701,#700);
#703=EDGE_CURVE('E383',#696,#251,#702,.F.);
#704=ORIENTED_EDGE('',*,*,#703,.T.);
#705=ORIENTED_EDGE('',*,*,#265,.F.);
#706=ORIENTED_EDGE('',*,*,#228,.F.);
#707=EDGE_LOOP('',(#681,#690,#698,#704,#705,#706));
#708=FACE_BOUND('',#707,.T.);
#709=ADVANCED_FACE('F381',(#708),#673,.F.);
#710=CARTESIAN_POINT('',(38.63875,15.5,0.));
#711=DIRECTION('',(1.,0.,0.));
#712=DIRECTION('',(0.,1.,0.));
#713=AXIS2_PLACEMENT_3D('',#710,#711,#712);
#714=PLANE('',#713);
#715=DIRECTION('',(0.,0.979079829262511,0.203476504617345));
#716=VECTOR('',#715,1.);
#717=CARTESIAN_POINT('',(38.63875,5.5926726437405,11.2957265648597));
#718=LINE('',#717,#716);
#719=CARTESIAN_POINT('',(38.63875,-3.0807363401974,9.49318208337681));
#720=VERTEX_POINT('',#719);
#721=CARTESIAN_POINT('',(38.63875,5.5926726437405,11.2957265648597));
#722=VERTEX_POINT('',#721);
#723=EDGE_CURVE('E396',#720,#722,#718,.T.);
#724=ORIENTED_EDGE('',*,*,#723,.F.);
#725=CARTESIAN_POINT('',(38.63875,-1.75,3.09));
#726=DIRECTION('',(1.,0.,0.));
#727=DIRECTION('',(0.,1.,0.));
#728=AXIS2_PLACEMENT_3D('',#725,#726,#727);
#729=CIRCLE('',#728,6.54);
#730=CARTESIAN_POINT('',(38.63875,-8.2844566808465,3.35921345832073));
#731=VERTEX_POINT('',#730);
#732=EDGE_CURVE('E671',#731,#720,#729,.F.);
#733=ORIENTED_EDGE('',*,*,#732,.F.);
#734=DIRECTION('',(0.,1.,0.));
#735=VECTOR('',#734,1.);
#736=CARTESIAN_POINT('',(38.63875,15.5,3.35921345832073));
#737=LINE('',#736,#735);
#738=EDGE_CURVE('E380',#731,#626,#737,.T.);
#739=ORIENTED_EDGE('',*,*,#738,.T.);
#740=ORIENTED_EDGE('',*,*,#627,.T.);
#741=ORIENTED_EDGE('',*,*,#664,.T.);
#742=DIRECTION('',(0.,0.,1.));
#743=VECTOR('',#742,1.);
#744=CARTESIAN_POINT('',(38.63875,5.5926726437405,10.2743593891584));
#745=LINE('',#744,#743);
#746=EDGE_CURVE('E402',#657,#722,#745,.T.);
#747=ORIENTED_EDGE('',*,*,#746,.T.);
#748=EDGE_LOOP('',(#724,#733,#739,#740,#741,#747));
#749=FACE_BOUND('',#748,.T.);
#750=ADVANCED_FACE('F1199',(#749),#714,.T.);
#751=CARTESIAN_POINT('',(38.63875,5.5926726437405,11.2957265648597));
#752=DIRECTION('',(0.,-0.203476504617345,0.979079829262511));
#753=DIRECTION('',(0.,0.979079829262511,0.203476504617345));
#754=AXIS2_PLACEMENT_3D('',#751,#752,#753);
#755=PLANE('',#754);
#756=ORIENTED_EDGE('',*,*,#723,.T.);
#757=DIRECTION('',(-1.,0.,0.));
#758=VECTOR('',#757,1.);
#759=CARTESIAN_POINT('',(38.7625,5.5926726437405,11.2957265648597));
#760=LINE('',#759,#758);
#761=EDGE_CURVE('E422',#722,#696,#760,.T.);
#762=ORIENTED_EDGE('',*,*,#761,.T.);
#763=ORIENTED_EDGE('',*,*,#697,.T.);
#764=DIRECTION('',(1.,0.,0.));
#765=VECTOR('',#764,1.);
#766=CARTESIAN_POINT('',(38.63875,-3.0807363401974,9.49318208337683));
#767=LINE('',#766,#765);
#768=EDGE_CURVE('E525',#720,#688,#767,.F.);
#769=ORIENTED_EDGE('',*,*,#768,.F.);
#770=EDGE_LOOP('',(#756,#762,#763,#769));
#771=FACE_BOUND('',#770,.T.);
#772=ADVANCED_FACE('F766',(#771),#755,.T.);
#773=CARTESIAN_POINT('',(2.8867513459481,-5.,2.2));
#774=DIRECTION('',(0.,-1.,0.));
#775=DIRECTION('',(1.,0.,0.));
#776=AXIS2_PLACEMENT_3D('',#773,#774,#775);
#777=PLANE('',#776);
#778=DIRECTION('',(0.,0.,1.));
#779=VECTOR('',#778,1.);
#780=CARTESIAN_POINT('',(2.88675134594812,-5.,2.2));
#781=LINE('',#780,#779);
#782=CARTESIAN_POINT('',(2.8867513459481,-5.,2.2));
#783=VERTEX_POINT('',#782);
#784=EDGE_CURVE('E744',#85,#783,#781,.F.);
#785=ORIENTED_EDGE('',*,*,#784,.T.);
#786=DIRECTION('',(-1.,0.,0.));
#787=VECTOR('',#786,1.);
#788=CARTESIAN_POINT('',(15.25,-5.,2.2));
#789=LINE('',#788,#787);
#790=CARTESIAN_POINT('',(-2.8867513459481,-5.,2.2));
#791=VERTEX_POINT('',#790);
#792=EDGE_CURVE('E521',#791,#783,#789,.F.);
#793=ORIENTED_EDGE('',*,*,#792,.F.);
#794=DIRECTION('',(0.,0.,1.));
#795=VECTOR('',#794,1.);
#796=CARTESIAN_POINT('',(-2.8867513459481,-5.,2.2));
#797=LINE('',#796,#795);
#798=EDGE_CURVE('E542',#791,#87,#797,.T.);
#799=ORIENTED_EDGE('',*,*,#798,.T.);
#800=ORIENTED_EDGE('',*,*,#88,.F.);
#801=EDGE_LOOP('',(#785,#793,#799,#800));
#802=FACE_BOUND('',#801,.T.);
#803=ADVANCED_FACE('F818',(#802),#777,.F.);
#804=CARTESIAN_POINT('',(5.77350269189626,0.,2.2));
#805=DIRECTION('',(0.866025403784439,-0.5,0.));
#806=DIRECTION('',(0.5,0.866025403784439,0.));
#807=AXIS2_PLACEMENT_3D('',#804,#805,#806);
#808=PLANE('',#807);
#809=DIRECTION('',(0.,0.,1.));
#810=VECTOR('',#809,1.);
#811=CARTESIAN_POINT('',(5.77350269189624,0.,2.2));
#812=LINE('',#811,#810);
#813=CARTESIAN_POINT('',(5.77350269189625,0.,2.2));
#814=VERTEX_POINT('',#813);
#815=EDGE_CURVE('E570',#39,#814,#812,.F.);
#816=ORIENTED_EDGE('',*,*,#815,.T.);
#817=DIRECTION('',(0.5,0.866025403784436,0.));
#818=VECTOR('',#817,1.);
#819=CARTESIAN_POINT('',(2.8867513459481,-5.,2.2));
#820=LINE('',#819,#818);
#821=EDGE_CURVE('E524',#783,#814,#820,.T.);
#822=ORIENTED_EDGE('',*,*,#821,.F.);
#823=ORIENTED_EDGE('',*,*,#784,.F.);
#824=ORIENTED_EDGE('',*,*,#103,.F.);
#825=ORIENTED_EDGE('',*,*,#48,.F.);
#826=EDGE_LOOP('',(#816,#822,#823,#824,#825));
#827=FACE_BOUND('',#826,.T.);
#828=ADVANCED_FACE('F822',(#827),#808,.F.);
#829=CARTESIAN_POINT('',(2.8867513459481,5.,2.2));
#830=DIRECTION('',(0.866025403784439,0.5,0.));
#831=DIRECTION('',(-0.5,0.866025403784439,0.));
#832=AXIS2_PLACEMENT_3D('',#829,#830,#831);
#833=PLANE('',#832);
#834=DIRECTION('',(0.,0.,1.));
#835=VECTOR('',#834,1.);
#836=CARTESIAN_POINT('',(2.8867513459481,5.,2.2));
#837=LINE('',#836,#835);
#838=CARTESIAN_POINT('',(2.8867513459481,5.,2.2));
#839=VERTEX_POINT('',#838);
#840=EDGE_CURVE('E551',#31,#839,#837,.F.);
#841=ORIENTED_EDGE('',*,*,#840,.T.);
#842=DIRECTION('',(-0.5,0.866025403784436,0.));
#843=VECTOR('',#842,1.);
#844=CARTESIAN_POINT('',(5.77350269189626,0.,2.2));
#845=LINE('',#844,#843);
#846=EDGE_CURVE('E561',#814,#839,#845,.T.);
#847=ORIENTED_EDGE('',*,*,#846,.F.);
#848=ORIENTED_EDGE('',*,*,#815,.F.);
#849=ORIENTED_EDGE('',*,*,#40,.F.);
#850=EDGE_LOOP('',(#841,#847,#848,#849));
#851=FACE_BOUND('',#850,.T.);
#852=ADVANCED_FACE('F840',(#851),#833,.F.);
#853=CARTESIAN_POINT('',(-2.8867513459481,5.,2.2));
#854=DIRECTION('',(0.,1.,0.));
#855=DIRECTION('',(-1.,0.,0.));
#856=AXIS2_PLACEMENT_3D('',#853,#854,#855);
#857=PLANE('',#856);
#858=DIRECTION('',(0.,0.,1.));
#859=VECTOR('',#858,1.);
#860=CARTESIAN_POINT('',(-2.88675134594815,5.,2.2));
#861=LINE('',#860,#859);
#862=CARTESIAN_POINT('',(-2.88675134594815,5.,2.2));
#863=VERTEX_POINT('',#862);
#864=EDGE_CURVE('E537',#29,#863,#861,.F.);
#865=ORIENTED_EDGE('',*,*,#864,.T.);
#866=DIRECTION('',(-1.,0.,0.));
#867=VECTOR('',#866,1.);
#868=CARTESIAN_POINT('',(15.25,5.,2.2));
#869=LINE('',#868,#867);
#870=EDGE_CURVE('E556',#839,#863,#869,.T.);
#871=ORIENTED_EDGE('',*,*,#870,.F.);
#872=ORIENTED_EDGE('',*,*,#840,.F.);
#873=ORIENTED_EDGE('',*,*,#32,.F.);
#874=EDGE_LOOP('',(#865,#871,#872,#873));
#875=FACE_BOUND('',#874,.T.);
#876=ADVANCED_FACE('F843',(#875),#857,.F.);
#877=CARTESIAN_POINT('',(-5.7735026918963,0.,2.2));
#878=DIRECTION('',(-0.866025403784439,0.5,0.));
#879=DIRECTION('',(-0.5,-0.866025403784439,0.));
#880=AXIS2_PLACEMENT_3D('',#877,#878,#879);
#881=PLANE('',#880);
#882=DIRECTION('',(0.,0.,1.));
#883=VECTOR('',#882,1.);
#884=CARTESIAN_POINT('',(-5.77350269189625,0.,2.2));
#885=LINE('',#884,#883);
#886=CARTESIAN_POINT('',(-5.7735026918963,0.,2.2));
#887=VERTEX_POINT('',#886);
#888=EDGE_CURVE('E540',#63,#887,#885,.F.);
#889=ORIENTED_EDGE('',*,*,#888,.T.);
#890=DIRECTION('',(-0.500000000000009,-0.866025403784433,0.));
#891=VECTOR('',#890,1.);
#892=CARTESIAN_POINT('',(-2.8867513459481,5.,2.2));
#893=LINE('',#892,#891);
#894=EDGE_CURVE('E530',#863,#887,#893,.T.);
#895=ORIENTED_EDGE('',*,*,#894,.F.);
#896=ORIENTED_EDGE('',*,*,#864,.F.);
#897=ORIENTED_EDGE('',*,*,#70,.F.);
#898=EDGE_LOOP('',(#889,#895,#896,#897));
#899=FACE_BOUND('',#898,.T.);
#900=ADVANCED_FACE('F847',(#899),#881,.F.);
#901=CARTESIAN_POINT('',(-2.8867513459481,-5.,2.2));
#902=DIRECTION('',(-0.866025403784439,-0.5,0.));
#903=DIRECTION('',(0.5,-0.866025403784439,0.));
#904=AXIS2_PLACEMENT_3D('',#901,#902,#903);
#905=PLANE('',#904);
#906=ORIENTED_EDGE('',*,*,#798,.F.);
#907=DIRECTION('',(0.500000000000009,-0.866025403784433,0.));
#908=VECTOR('',#907,1.);
#909=CARTESIAN_POINT('',(-5.7735026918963,0.,2.2));
#910=LINE('',#909,#908);
#911=EDGE_CURVE('E462',#887,#791,#910,.T.);
#912=ORIENTED_EDGE('',*,*,#911,.F.);
#913=ORIENTED_EDGE('',*,*,#888,.F.);
#914=ORIENTED_EDGE('',*,*,#64,.F.);
#915=ORIENTED_EDGE('',*,*,#95,.F.);
#916=EDGE_LOOP('',(#906,#912,#913,#914,#915));
#917=FACE_BOUND('',#916,.T.);
#918=ADVANCED_FACE('F832',(#917),#905,.F.);
#919=CARTESIAN_POINT('',(33.3867513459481,-5.,2.2));
#920=DIRECTION('',(0.,-1.,0.));
#921=DIRECTION('',(1.,0.,0.));
#922=AXIS2_PLACEMENT_3D('',#919,#920,#921);
#923=PLANE('',#922);
#924=DIRECTION('',(0.,0.,1.));
#925=VECTOR('',#924,1.);
#926=CARTESIAN_POINT('',(33.3867513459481,-5.,2.2));
#927=LINE('',#926,#925);
#928=CARTESIAN_POINT('',(33.3867513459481,-5.,2.2));
#929=VERTEX_POINT('',#928);
#930=EDGE_CURVE('E741',#129,#929,#927,.F.);
#931=ORIENTED_EDGE('',*,*,#930,.T.);
#932=DIRECTION('',(-1.,0.,0.));
#933=VECTOR('',#932,1.);
#934=CARTESIAN_POINT('',(15.25,-5.,2.2));
#935=LINE('',#934,#933);
#936=CARTESIAN_POINT('',(27.6132486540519,-5.,2.2));
#937=VERTEX_POINT('',#936);
#938=EDGE_CURVE('E458',#937,#929,#935,.F.);
#939=ORIENTED_EDGE('',*,*,#938,.F.);
#940=DIRECTION('',(0.,0.,1.));
#941=VECTOR('',#940,1.);
#942=CARTESIAN_POINT('',(27.6132486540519,-5.,2.2));
#943=LINE('',#942,#941);
#944=EDGE_CURVE('E450',#937,#137,#943,.T.);
#945=ORIENTED_EDGE('',*,*,#944,.T.);
#946=ORIENTED_EDGE('',*,*,#138,.F.);
#947=EDGE_LOOP('',(#931,#939,#945,#946));
#948=FACE_BOUND('',#947,.T.);
#949=ADVANCED_FACE('F856',(#948),#923,.F.);
#950=CARTESIAN_POINT('',(36.2735026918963,0.,2.2));
#951=DIRECTION('',(0.866025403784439,-0.5,0.));
#952=DIRECTION('',(0.5,0.866025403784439,0.));
#953=AXIS2_PLACEMENT_3D('',#950,#951,#952);
#954=PLANE('',#953);
#955=DIRECTION('',(0.,0.,1.));
#956=VECTOR('',#955,1.);
#957=CARTESIAN_POINT('',(36.2735026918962,0.,2.2));
#958=LINE('',#957,#956);
#959=CARTESIAN_POINT('',(36.2735026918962,0.,2.2));
#960=VERTEX_POINT('',#959);
#961=EDGE_CURVE('E502',#160,#960,#958,.F.);
#962=ORIENTED_EDGE('',*,*,#961,.T.);
#963=DIRECTION('',(0.500000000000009,0.866025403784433,0.));
#964=VECTOR('',#963,1.);
#965=CARTESIAN_POINT('',(33.3867513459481,-5.,2.2));
#966=LINE('',#965,#964);
#967=EDGE_CURVE('E461',#929,#960,#966,.T.);
#968=ORIENTED_EDGE('',*,*,#967,.F.);
#969=ORIENTED_EDGE('',*,*,#930,.F.);
#970=ORIENTED_EDGE('',*,*,#130,.F.);
#971=ORIENTED_EDGE('',*,*,#161,.F.);
#972=EDGE_LOOP('',(#962,#968,#969,#970,#971));
#973=FACE_BOUND('',#972,.T.);
#974=ADVANCED_FACE('F1016',(#973),#954,.F.);
#975=CARTESIAN_POINT('',(33.3867513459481,5.,2.2));
#976=DIRECTION('',(0.866025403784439,0.5,0.));
#977=DIRECTION('',(-0.5,0.866025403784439,0.));
#978=AXIS2_PLACEMENT_3D('',#975,#976,#977);
#979=PLANE('',#978);
#980=DIRECTION('',(0.,0.,1.));
#981=VECTOR('',#980,1.);
#982=CARTESIAN_POINT('',(33.3867513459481,5.,2.2));
#983=LINE('',#982,#981);
#984=CARTESIAN_POINT('',(33.3867513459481,5.,2.2));
#985=VERTEX_POINT('',#984);
#986=EDGE_CURVE('E488',#185,#985,#983,.F.);
#987=ORIENTED_EDGE('',*,*,#986,.T.);
#988=DIRECTION('',(-0.500000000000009,0.866025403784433,0.));
#989=VECTOR('',#988,1.);
#990=CARTESIAN_POINT('',(36.2735026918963,0.,2.2));
#991=LINE('',#990,#989);
#992=EDGE_CURVE('E493',#960,#985,#991,.T.);
#993=ORIENTED_EDGE('',*,*,#992,.F.);
#994=ORIENTED_EDGE('',*,*,#961,.F.);
#995=ORIENTED_EDGE('',*,*,#192,.F.);
#996=EDGE_LOOP('',(#987,#993,#994,#995));
#997=FACE_BOUND('',#996,.T.);
#998=ADVANCED_FACE('F1012',(#997),#979,.F.);
#999=CARTESIAN_POINT('',(27.6132486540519,5.,2.2));
#1000=DIRECTION('',(0.,1.,0.));
#1001=DIRECTION('',(-1.,0.,0.));
#1002=AXIS2_PLACEMENT_3D('',#999,#1000,#1001);
#1003=PLANE('',#1002);
#1004=DIRECTION('',(0.,0.,1.));
#1005=VECTOR('',#1004,1.);
#1006=CARTESIAN_POINT('',(27.6132486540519,5.,2.2));
#1007=LINE('',#1006,#1005);
#1008=CARTESIAN_POINT('',(27.6132486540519,5.,2.2));
#1009=VERTEX_POINT('',#1008);
#1010=EDGE_CURVE('E474',#177,#1009,#1007,.F.);
#1011=ORIENTED_EDGE('',*,*,#1010,.T.);
#1012=DIRECTION('',(-1.,0.,0.));
#1013=VECTOR('',#1012,1.);
#1014=CARTESIAN_POINT('',(15.25,5.,2.2));
#1015=LINE('',#1014,#1013);
#1016=EDGE_CURVE('E479',#985,#1009,#1015,.T.);
#1017=ORIENTED_EDGE('',*,*,#1016,.F.);
#1018=ORIENTED_EDGE('',*,*,#986,.F.);
#1019=ORIENTED_EDGE('',*,*,#186,.F.);
#1020=EDGE_LOOP('',(#1011,#1017,#1018,#1019));
#1021=FACE_BOUND('',#1020,.T.);
#1022=ADVANCED_FACE('F1008',(#1021),#1003,.F.);
#1023=CARTESIAN_POINT('',(24.7264973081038,0.,2.2));
#1024=DIRECTION('',(-0.866025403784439,0.5,0.));
#1025=DIRECTION('',(-0.5,-0.866025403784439,0.));
#1026=AXIS2_PLACEMENT_3D('',#1023,#1024,#1025);
#1027=PLANE('',#1026);
#1028=DIRECTION('',(0.,0.,1.));
#1029=VECTOR('',#1028,1.);
#1030=CARTESIAN_POINT('',(24.7264973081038,0.,2.2));
#1031=LINE('',#1030,#1029);
#1032=CARTESIAN_POINT('',(24.7264973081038,0.,2.2));
#1033=VERTEX_POINT('',#1032);
#1034=EDGE_CURVE('E448',#169,#1033,#1031,.F.);
#1035=ORIENTED_EDGE('',*,*,#1034,.T.);
#1036=DIRECTION('',(-0.5,-0.866025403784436,0.));
#1037=VECTOR('',#1036,1.);
#1038=CARTESIAN_POINT('',(27.6132486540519,5.,2.2));
#1039=LINE('',#1038,#1037);
#1040=EDGE_CURVE('E469',#1009,#1033,#1039,.T.);
#1041=ORIENTED_EDGE('',*,*,#1040,.F.);
#1042=ORIENTED_EDGE('',*,*,#1010,.F.);
#1043=ORIENTED_EDGE('',*,*,#178,.F.);
#1044=EDGE_LOOP('',(#1035,#1041,#1042,#1043));
#1045=FACE_BOUND('',#1044,.T.);
#1046=ADVANCED_FACE('F1004',(#1045),#1027,.F.);
#1047=CARTESIAN_POINT('',(27.6132486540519,-5.,2.2));
#1048=DIRECTION('',(-0.866025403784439,-0.5,0.));
#1049=DIRECTION('',(0.5,-0.866025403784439,0.));
#1050=AXIS2_PLACEMENT_3D('',#1047,#1048,#1049);
#1051=PLANE('',#1050);
#1052=ORIENTED_EDGE('',*,*,#145,.F.);
#1053=ORIENTED_EDGE('',*,*,#944,.F.);
#1054=DIRECTION('',(0.5,-0.866025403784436,0.));
#1055=VECTOR('',#1054,1.);
#1056=CARTESIAN_POINT('',(24.7264973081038,0.,2.2));
#1057=LINE('',#1056,#1055);
#1058=EDGE_CURVE('E465',#1033,#937,#1057,.T.);
#1059=ORIENTED_EDGE('',*,*,#1058,.F.);
#1060=ORIENTED_EDGE('',*,*,#1034,.F.);
#1061=ORIENTED_EDGE('',*,*,#170,.F.);
#1062=EDGE_LOOP('',(#1052,#1053,#1059,#1060,#1061));
#1063=FACE_BOUND('',#1062,.T.);
#1064=ADVANCED_FACE('F1001',(#1063),#1051,.F.);
#1065=CARTESIAN_POINT('',(-8.2625,15.5,0.));
#1066=DIRECTION('',(1.,0.,0.));
#1067=DIRECTION('',(0.,1.,0.));
#1068=AXIS2_PLACEMENT_3D('',#1065,#1066,#1067);
#1069=PLANE('',#1068);
#1070=ORIENTED_EDGE('',*,*,#258,.T.);
#1071=DIRECTION('',(0.,0.,1.));
#1072=VECTOR('',#1071,1.);
#1073=CARTESIAN_POINT('',(-8.2625,5.5926726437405,10.2743593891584));
#1074=LINE('',#1073,#1072);
#1075=CARTESIAN_POINT('',(-8.2625,5.59267264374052,11.5));
#1076=VERTEX_POINT('',#1075);
#1077=EDGE_CURVE('E773',#249,#1076,#1074,.T.);
#1078=ORIENTED_EDGE('',*,*,#1077,.T.);
#1079=DIRECTION('',(0.,0.979079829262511,0.203476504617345));
#1080=VECTOR('',#1079,1.);
#1081=CARTESIAN_POINT('',(-8.2625,5.59267264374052,11.5));
#1082=LINE('',#1081,#1080);
#1083=CARTESIAN_POINT('',(-8.2625,-3.1214316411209,9.68899804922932));
#1084=VERTEX_POINT('',#1083);
#1085=EDGE_CURVE('E468',#1084,#1076,#1082,.T.);
#1086=ORIENTED_EDGE('',*,*,#1085,.F.);
#1087=CARTESIAN_POINT('',(-8.2625,-1.75,3.09));
#1088=DIRECTION('',(1.,0.,0.));
#1089=DIRECTION('',(0.,1.,0.));
#1090=AXIS2_PLACEMENT_3D('',#1087,#1088,#1089);
#1091=CIRCLE('',#1090,6.74);
#1092=CARTESIAN_POINT('',(-8.2625,-8.4846213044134,3.35921345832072));
#1093=VERTEX_POINT('',#1092);
#1094=EDGE_CURVE('E668',#1093,#1084,#1091,.F.);
#1095=ORIENTED_EDGE('',*,*,#1094,.F.);
#1096=DIRECTION('',(0.,1.,0.));
#1097=VECTOR('',#1096,1.);
#1098=CARTESIAN_POINT('',(-8.2625,15.5,3.35921345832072));
#1099=LINE('',#1098,#1097);
#1100=EDGE_CURVE('E736',#1093,#208,#1099,.T.);
#1101=ORIENTED_EDGE('',*,*,#1100,.T.);
#1102=ORIENTED_EDGE('',*,*,#211,.T.);
#1103=EDGE_LOOP('',(#1070,#1078,#1086,#1095,#1101,#1102));
#1104=FACE_BOUND('',#1103,.T.);
#1105=ADVANCED_FACE('F775',(#1104),#1069,.T.);
#1106=CARTESIAN_POINT('',(-1.35,15.5,0.));
#1107=DIRECTION('',(1.,0.,0.));
#1108=DIRECTION('',(0.,1.,0.));
#1109=AXIS2_PLACEMENT_3D('',#1106,#1107,#1108);
#1110=PLANE('',#1109);
#1111=ORIENTED_EDGE('',*,*,#431,.F.);
#1112=CARTESIAN_POINT('',(-1.35,15.5,11.5));
#1113=DIRECTION('',(1.,0.,0.));
#1114=DIRECTION('',(0.,1.,0.));
#1115=AXIS2_PLACEMENT_3D('',#1112,#1113,#1114);
#1116=CIRCLE('',#1115,5.);
#1117=CARTESIAN_POINT('',(-1.35,18.5073278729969,7.5055064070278));
#1118=VERTEX_POINT('',#1117);
#1119=EDGE_CURVE('E438',#1118,#422,#1116,.T.);
#1120=ORIENTED_EDGE('',*,*,#1119,.F.);
#1121=DIRECTION('',(0.,-0.798898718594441,-0.601465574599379));
#1122=VECTOR('',#1121,1.);
#1123=CARTESIAN_POINT('',(-1.35,13.,3.35921345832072));
#1124=LINE('',#1123,#1122);
#1125=CARTESIAN_POINT('',(-1.35,13.,3.35921345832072));
#1126=VERTEX_POINT('',#1125);
#1127=EDGE_CURVE('E1567',#1126,#1118,#1124,.F.);
#1128=ORIENTED_EDGE('',*,*,#1127,.F.);
#1129=CARTESIAN_POINT('',(-1.35,-8.87,-9.1));
#1130=DIRECTION('',(1.,0.,0.));
#1131=DIRECTION('',(0.,1.,0.));
#1132=AXIS2_PLACEMENT_3D('',#1129,#1130,#1131);
#1133=CIRCLE('',#1132,25.17);
#1134=EDGE_CURVE('E663',#430,#1126,#1133,.F.);
#1135=ORIENTED_EDGE('',*,*,#1134,.F.);
#1136=EDGE_LOOP('',(#1111,#1120,#1128,#1135));
#1137=FACE_BOUND('',#1136,.T.);
#1138=ORIENTED_EDGE('',*,*,#301,.F.);
#1139=ORIENTED_EDGE('',*,*,#322,.F.);
#1140=EDGE_LOOP('',(#1138,#1139));
#1141=FACE_BOUND('',#1140,.T.);
#1142=ADVANCED_FACE('F994',(#1137,#1141),#1110,.F.);
#1143=CARTESIAN_POINT('',(6.8,15.5,11.5));
#1144=DIRECTION('',(1.,0.,0.));
#1145=DIRECTION('',(0.,1.,0.));
#1146=AXIS2_PLACEMENT_3D('',#1143,#1144,#1145);
#1147=CYLINDRICAL_SURFACE('',#1146,5.);
#1148=CARTESIAN_POINT('',(6.8,15.5,11.5));
#1149=DIRECTION('',(1.,0.,0.));
#1150=DIRECTION('',(0.,1.,0.));
#1151=AXIS2_PLACEMENT_3D('',#1148,#1149,#1150);
#1152=CIRCLE('',#1151,5.);
#1153=CARTESIAN_POINT('',(6.8,18.5073278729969,7.5055064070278));
#1154=VERTEX_POINT('',#1153);
#1155=EDGE_CURVE('E437',#1154,#412,#1152,.T.);
#1156=ORIENTED_EDGE('',*,*,#1155,.F.);
#1157=DIRECTION('',(-1.,0.,0.));
#1158=VECTOR('',#1157,1.);
#1159=CARTESIAN_POINT('',(6.8,18.5073278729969,7.5055064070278));
#1160=LINE('',#1159,#1158);
#1161=EDGE_CURVE('E1564',#1118,#1154,#1160,.F.);
#1162=ORIENTED_EDGE('',*,*,#1161,.F.);
#1163=ORIENTED_EDGE('',*,*,#1119,.T.);
#1164=ORIENTED_EDGE('',*,*,#423,.T.);
#1165=EDGE_LOOP('',(#1156,#1162,#1163,#1164));
#1166=FACE_BOUND('',#1165,.T.);
#1167=ADVANCED_FACE('F990',(#1166),#1147,.T.);
#1168=CARTESIAN_POINT('',(6.8,15.5,0.));
#1169=DIRECTION('',(1.,0.,0.));
#1170=DIRECTION('',(0.,1.,0.));
#1171=AXIS2_PLACEMENT_3D('',#1168,#1169,#1170);
#1172=PLANE('',#1171);
#1173=ORIENTED_EDGE('',*,*,#284,.T.);
#1174=ORIENTED_EDGE('',*,*,#330,.T.);
#1175=EDGE_LOOP('',(#1173,#1174));
#1176=FACE_BOUND('',#1175,.T.);
#1177=ORIENTED_EDGE('',*,*,#1155,.T.);
#1178=ORIENTED_EDGE('',*,*,#415,.T.);
#1179=CARTESIAN_POINT('',(6.8,-8.87,-9.1));
#1180=DIRECTION('',(1.,0.,0.));
#1181=DIRECTION('',(0.,1.,0.));
#1182=AXIS2_PLACEMENT_3D('',#1179,#1180,#1181);
#1183=CIRCLE('',#1182,25.17);
#1184=CARTESIAN_POINT('',(6.8,13.,3.35921345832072));
#1185=VERTEX_POINT('',#1184);
#1186=EDGE_CURVE('E659',#1185,#414,#1183,.T.);
#1187=ORIENTED_EDGE('',*,*,#1186,.F.);
#1188=DIRECTION('',(0.,-0.798898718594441,-0.601465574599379));
#1189=VECTOR('',#1188,1.);
#1190=CARTESIAN_POINT('',(6.8,13.,3.35921345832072));
#1191=LINE('',#1190,#1189);
#1192=EDGE_CURVE('E662',#1154,#1185,#1191,.T.);
#1193=ORIENTED_EDGE('',*,*,#1192,.F.);
#1194=EDGE_LOOP('',(#1177,#1178,#1187,#1193));
#1195=FACE_BOUND('',#1194,.T.);
#1196=ADVANCED_FACE('F986',(#1176,#1195),#1172,.T.);
#1197=CARTESIAN_POINT('',(15.35,15.5,0.));
#1198=DIRECTION('',(1.,0.,0.));
#1199=DIRECTION('',(0.,1.,0.));
#1200=AXIS2_PLACEMENT_3D('',#1197,#1198,#1199);
#1201=PLANE('',#1200);
#1202=ORIENTED_EDGE('',*,*,#388,.F.);
#1203=ORIENTED_EDGE('',*,*,#367,.F.);
#1204=EDGE_LOOP('',(#1202,#1203));
#1205=FACE_BOUND('',#1204,.T.);
#1206=ORIENTED_EDGE('',*,*,#455,.F.);
#1207=CARTESIAN_POINT('',(15.35,15.5,11.5));
#1208=DIRECTION('',(-1.,0.,0.));
#1209=DIRECTION('',(0.,-1.,0.));
#1210=AXIS2_PLACEMENT_3D('',#1207,#1208,#1209);
#1211=CIRCLE('',#1210,5.);
#1212=CARTESIAN_POINT('',(15.35,18.5073278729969,7.5055064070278));
#1213=VERTEX_POINT('',#1212);
#1214=EDGE_CURVE('E428',#1213,#452,#1211,.F.);
#1215=ORIENTED_EDGE('',*,*,#1214,.F.);
#1216=DIRECTION('',(0.,-0.798898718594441,-0.601465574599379));
#1217=VECTOR('',#1216,1.);
#1218=CARTESIAN_POINT('',(15.35,18.5073278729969,7.5055064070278));
#1219=LINE('',#1218,#1217);
#1220=CARTESIAN_POINT('',(15.35,13.,3.35921345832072));
#1221=VERTEX_POINT('',#1220);
#1222=EDGE_CURVE('E1558',#1221,#1213,#1219,.F.);
#1223=ORIENTED_EDGE('',*,*,#1222,.F.);
#1224=CARTESIAN_POINT('',(15.35,-8.87,-9.1));
#1225=DIRECTION('',(1.,0.,0.));
#1226=DIRECTION('',(0.,1.,0.));
#1227=AXIS2_PLACEMENT_3D('',#1224,#1225,#1226);
#1228=CIRCLE('',#1227,25.17);
#1229=EDGE_CURVE('E654',#454,#1221,#1228,.F.);
#1230=ORIENTED_EDGE('',*,*,#1229,.F.);
#1231=EDGE_LOOP('',(#1206,#1215,#1223,#1230));
#1232=FACE_BOUND('',#1231,.T.);
#1233=ADVANCED_FACE('F982',(#1205,#1232),#1201,.F.);
#1234=CARTESIAN_POINT('',(15.35,15.5,11.5));
#1235=DIRECTION('',(-1.,0.,0.));
#1236=DIRECTION('',(0.,-1.,0.));
#1237=AXIS2_PLACEMENT_3D('',#1234,#1235,#1236);
#1238=CYLINDRICAL_SURFACE('',#1237,5.);
#1239=ORIENTED_EDGE('',*,*,#1214,.T.);
#1240=ORIENTED_EDGE('',*,*,#477,.T.);
#1241=CARTESIAN_POINT('',(23.5,15.5,11.5));
#1242=DIRECTION('',(-1.,0.,0.));
#1243=DIRECTION('',(0.,-1.,0.));
#1244=AXIS2_PLACEMENT_3D('',#1241,#1242,#1243);
#1245=CIRCLE('',#1244,5.);
#1246=CARTESIAN_POINT('',(23.5,18.5073278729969,7.5055064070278));
#1247=VERTEX_POINT('',#1246);
#1248=EDGE_CURVE('E699',#1247,#470,#1245,.F.);
#1249=ORIENTED_EDGE('',*,*,#1248,.F.);
#1250=DIRECTION('',(-1.,0.,0.));
#1251=VECTOR('',#1250,1.);
#1252=CARTESIAN_POINT('',(15.35,18.5073278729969,7.5055064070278));
#1253=LINE('',#1252,#1251);
#1254=EDGE_CURVE('E653',#1213,#1247,#1253,.F.);
#1255=ORIENTED_EDGE('',*,*,#1254,.F.);
#1256=EDGE_LOOP('',(#1239,#1240,#1249,#1255));
#1257=FACE_BOUND('',#1256,.T.);
#1258=ADVANCED_FACE('F978',(#1257),#1238,.T.);
#1259=CARTESIAN_POINT('',(23.5,15.5,0.));
#1260=DIRECTION('',(1.,0.,0.));
#1261=DIRECTION('',(0.,1.,0.));
#1262=AXIS2_PLACEMENT_3D('',#1259,#1260,#1261);
#1263=PLANE('',#1262);
#1264=ORIENTED_EDGE('',*,*,#1248,.T.);
#1265=ORIENTED_EDGE('',*,*,#471,.T.);
#1266=CARTESIAN_POINT('',(23.5,-8.87,-9.1));
#1267=DIRECTION('',(1.,0.,0.));
#1268=DIRECTION('',(0.,1.,0.));
#1269=AXIS2_PLACEMENT_3D('',#1266,#1267,#1268);
#1270=CIRCLE('',#1269,25.17);
#1271=CARTESIAN_POINT('',(23.5,13.,3.35921345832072));
#1272=VERTEX_POINT('',#1271);
#1273=EDGE_CURVE('E646',#1272,#462,#1270,.T.);
#1274=ORIENTED_EDGE('',*,*,#1273,.F.);
#1275=DIRECTION('',(0.,-0.798898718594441,-0.601465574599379));
#1276=VECTOR('',#1275,1.);
#1277=CARTESIAN_POINT('',(23.5,18.5073278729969,7.5055064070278));
#1278=LINE('',#1277,#1276);
#1279=EDGE_CURVE('E657',#1247,#1272,#1278,.T.);
#1280=ORIENTED_EDGE('',*,*,#1279,.F.);
#1281=EDGE_LOOP('',(#1264,#1265,#1274,#1280));
#1282=FACE_BOUND('',#1281,.T.);
#1283=ORIENTED_EDGE('',*,*,#350,.T.);
#1284=ORIENTED_EDGE('',*,*,#396,.T.);
#1285=EDGE_LOOP('',(#1283,#1284));
#1286=FACE_BOUND('',#1285,.T.);
#1287=ADVANCED_FACE('F975',(#1282,#1286),#1263,.T.);
#1288=CARTESIAN_POINT('',(38.7625,5.5926726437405,10.2743593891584));
#1289=DIRECTION('',(0.,1.,0.));
#1290=DIRECTION('',(-1.,0.,0.));
#1291=AXIS2_PLACEMENT_3D('',#1288,#1289,#1290);
#1292=PLANE('',#1291);
#1293=ORIENTED_EDGE('',*,*,#761,.F.);
#1294=ORIENTED_EDGE('',*,*,#746,.F.);
#1295=ORIENTED_EDGE('',*,*,#658,.F.);
#1296=DIRECTION('',(0.,0.,1.));
#1297=VECTOR('',#1296,1.);
#1298=CARTESIAN_POINT('',(38.7625,5.5926726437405,0.));
#1299=LINE('',#1298,#1297);
#1300=EDGE_CURVE('E677',#649,#560,#1299,.T.);
#1301=ORIENTED_EDGE('',*,*,#1300,.T.);
#1302=ORIENTED_EDGE('',*,*,#561,.F.);
#1303=DIRECTION('',(1.,0.,0.));
#1304=VECTOR('',#1303,1.);
#1305=CARTESIAN_POINT('',(40.,5.59267264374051,11.5));
#1306=LINE('',#1305,#1304);
#1307=EDGE_CURVE('E649',#462,#558,#1306,.T.);
#1308=ORIENTED_EDGE('',*,*,#1307,.F.);
#1309=ORIENTED_EDGE('',*,*,#463,.F.);
#1310=DIRECTION('',(1.,0.,0.));
#1311=VECTOR('',#1310,1.);
#1312=CARTESIAN_POINT('',(40.,5.59267264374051,11.5));
#1313=LINE('',#1312,#1311);
#1314=EDGE_CURVE('E658',#414,#454,#1313,.T.);
#1315=ORIENTED_EDGE('',*,*,#1314,.F.);
#1316=ORIENTED_EDGE('',*,*,#437,.F.);
#1317=DIRECTION('',(1.,0.,0.));
#1318=VECTOR('',#1317,1.);
#1319=CARTESIAN_POINT('',(40.,5.59267264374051,11.5));
#1320=LINE('',#1319,#1318);
#1321=EDGE_CURVE('E1572',#1076,#430,#1320,.T.);
#1322=ORIENTED_EDGE('',*,*,#1321,.F.);
#1323=ORIENTED_EDGE('',*,*,#1077,.F.);
#1324=ORIENTED_EDGE('',*,*,#252,.T.);
#1325=ORIENTED_EDGE('',*,*,#703,.F.);
#1326=EDGE_LOOP('',(#1293,#1294,#1295,#1301,#1302,#1308,#1309,#1315,#1316,#1322,#1323,#1324,#1325));
#1327=FACE_BOUND('',#1326,.T.);
#1328=ADVANCED_FACE('F769',(#1327),#1292,.F.);
#1329=CARTESIAN_POINT('',(32.05,15.5,0.));
#1330=DIRECTION('',(1.,0.,0.));
#1331=DIRECTION('',(0.,1.,0.));
#1332=AXIS2_PLACEMENT_3D('',#1329,#1330,#1331);
#1333=PLANE('',#1332);
#1334=ORIENTED_EDGE('',*,*,#534,.F.);
#1335=ORIENTED_EDGE('',*,*,#513,.F.);
#1336=EDGE_LOOP('',(#1334,#1335));
#1337=FACE_BOUND('',#1336,.T.);
#1338=ORIENTED_EDGE('',*,*,#591,.F.);
#1339=CARTESIAN_POINT('',(32.05,15.5,11.5));
#1340=DIRECTION('',(-1.,0.,0.));
#1341=DIRECTION('',(0.,-1.,0.));
#1342=AXIS2_PLACEMENT_3D('',#1339,#1340,#1341);
#1343=CIRCLE('',#1342,5.);
#1344=CARTESIAN_POINT('',(32.05,18.5073278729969,7.5055064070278));
#1345=VERTEX_POINT('',#1344);
#1346=EDGE_CURVE('E416',#1345,#584,#1343,.F.);
#1347=ORIENTED_EDGE('',*,*,#1346,.F.);
#1348=DIRECTION('',(0.,-0.798898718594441,-0.601465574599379));
#1349=VECTOR('',#1348,1.);
#1350=CARTESIAN_POINT('',(32.05,18.5073278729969,7.5055064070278));
#1351=LINE('',#1350,#1349);
#1352=CARTESIAN_POINT('',(32.05,13.,3.35921345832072));
#1353=VERTEX_POINT('',#1352);
#1354=EDGE_CURVE('E1542',#1353,#1345,#1351,.F.);
#1355=ORIENTED_EDGE('',*,*,#1354,.F.);
#1356=CARTESIAN_POINT('',(32.05,-8.87,-9.1));
#1357=DIRECTION('',(1.,0.,0.));
#1358=DIRECTION('',(0.,1.,0.));
#1359=AXIS2_PLACEMENT_3D('',#1356,#1357,#1358);
#1360=CIRCLE('',#1359,25.17);
#1361=EDGE_CURVE('E650',#558,#1353,#1360,.F.);
#1362=ORIENTED_EDGE('',*,*,#1361,.F.);
#1363=EDGE_LOOP('',(#1338,#1347,#1355,#1362));
#1364=FACE_BOUND('',#1363,.T.);
#1365=ADVANCED_FACE('F968',(#1337,#1364),#1333,.F.);
#1366=CARTESIAN_POINT('',(32.05,15.5,11.5));
#1367=DIRECTION('',(-1.,0.,0.));
#1368=DIRECTION('',(0.,-1.,0.));
#1369=AXIS2_PLACEMENT_3D('',#1366,#1367,#1368);
#1370=CYLINDRICAL_SURFACE('',#1369,5.);
#1371=ORIENTED_EDGE('',*,*,#1346,.T.);
#1372=ORIENTED_EDGE('',*,*,#585,.T.);
#1373=CARTESIAN_POINT('',(39.35,15.5,11.5));
#1374=DIRECTION('',(-1.,0.,0.));
#1375=DIRECTION('',(0.,-1.,0.));
#1376=AXIS2_PLACEMENT_3D('',#1373,#1374,#1375);
#1377=CIRCLE('',#1376,5.);
#1378=CARTESIAN_POINT('',(39.35,18.5073278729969,7.5055064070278));
#1379=VERTEX_POINT('',#1378);
#1380=EDGE_CURVE('E682',#1379,#576,#1377,.F.);
#1381=ORIENTED_EDGE('',*,*,#1380,.F.);
#1382=DIRECTION('',(-1.,0.,0.));
#1383=VECTOR('',#1382,1.);
#1384=CARTESIAN_POINT('',(32.05,18.5073278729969,7.5055064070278));
#1385=LINE('',#1384,#1383);
#1386=EDGE_CURVE('E645',#1345,#1379,#1385,.F.);
#1387=ORIENTED_EDGE('',*,*,#1386,.F.);
#1388=EDGE_LOOP('',(#1371,#1372,#1381,#1387));
#1389=FACE_BOUND('',#1388,.T.);
#1390=ADVANCED_FACE('F964',(#1389),#1370,.T.);
#1391=CARTESIAN_POINT('',(39.35,15.5,0.));
#1392=DIRECTION('',(1.,0.,0.));
#1393=DIRECTION('',(0.,1.,0.));
#1394=AXIS2_PLACEMENT_3D('',#1391,#1392,#1393);
#1395=PLANE('',#1394);
#1396=ORIENTED_EDGE('',*,*,#1380,.T.);
#1397=ORIENTED_EDGE('',*,*,#577,.T.);
#1398=CARTESIAN_POINT('',(39.35,-8.87,-9.1));
#1399=DIRECTION('',(1.,0.,0.));
#1400=DIRECTION('',(0.,1.,0.));
#1401=AXIS2_PLACEMENT_3D('',#1398,#1399,#1400);
#1402=CIRCLE('',#1401,25.17);
#1403=CARTESIAN_POINT('',(39.35,13.,3.35921345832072));
#1404=VERTEX_POINT('',#1403);
#1405=EDGE_CURVE('E641',#1404,#568,#1402,.T.);
#1406=ORIENTED_EDGE('',*,*,#1405,.F.);
#1407=DIRECTION('',(0.,-0.798898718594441,-0.601465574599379));
#1408=VECTOR('',#1407,1.);
#1409=CARTESIAN_POINT('',(39.35,18.5073278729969,7.5055064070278));
#1410=LINE('',#1409,#1408);
#1411=EDGE_CURVE('E1547',#1379,#1404,#1410,.T.);
#1412=ORIENTED_EDGE('',*,*,#1411,.F.);
#1413=EDGE_LOOP('',(#1396,#1397,#1406,#1412));
#1414=FACE_BOUND('',#1413,.T.);
#1415=ORIENTED_EDGE('',*,*,#496,.T.);
#1416=ORIENTED_EDGE('',*,*,#542,.T.);
#1417=EDGE_LOOP('',(#1415,#1416));
#1418=FACE_BOUND('',#1417,.T.);
#1419=ADVANCED_FACE('F960',(#1414,#1418),#1395,.T.);
#1420=CARTESIAN_POINT('',(38.7625,15.5,0.));
#1421=DIRECTION('',(1.,0.,0.));
#1422=DIRECTION('',(0.,1.,0.));
#1423=AXIS2_PLACEMENT_3D('',#1420,#1421,#1422);
#1424=PLANE('',#1423);
#1425=ORIENTED_EDGE('',*,*,#1300,.F.);
#1426=ORIENTED_EDGE('',*,*,#650,.F.);
#1427=ORIENTED_EDGE('',*,*,#610,.F.);
#1428=DIRECTION('',(0.,1.,0.));
#1429=VECTOR('',#1428,1.);
#1430=CARTESIAN_POINT('',(38.7625,15.5,3.35921345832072));
#1431=LINE('',#1430,#1429);
#1432=CARTESIAN_POINT('',(38.7625,-8.4846213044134,3.35921345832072));
#1433=VERTEX_POINT('',#1432);
#1434=EDGE_CURVE('E681',#1433,#607,#1431,.T.);
#1435=ORIENTED_EDGE('',*,*,#1434,.F.);
#1436=CARTESIAN_POINT('',(38.7625,-1.75,3.09));
#1437=DIRECTION('',(1.,0.,0.));
#1438=DIRECTION('',(0.,1.,0.));
#1439=AXIS2_PLACEMENT_3D('',#1436,#1437,#1438);
#1440=CIRCLE('',#1439,6.74);
#1441=CARTESIAN_POINT('',(38.7625,-3.1214316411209,9.68899804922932));
#1442=VERTEX_POINT('',#1441);
#1443=EDGE_CURVE('E636',#1442,#1433,#1440,.T.);
#1444=ORIENTED_EDGE('',*,*,#1443,.F.);
#1445=DIRECTION('',(0.,0.979079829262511,0.203476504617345));
#1446=VECTOR('',#1445,1.);
#1447=CARTESIAN_POINT('',(38.7625,5.59267264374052,11.5));
#1448=LINE('',#1447,#1446);
#1449=EDGE_CURVE('E644',#560,#1442,#1448,.F.);
#1450=ORIENTED_EDGE('',*,*,#1449,.F.);
#1451=EDGE_LOOP('',(#1425,#1426,#1427,#1435,#1444,#1450));
#1452=FACE_BOUND('',#1451,.T.);
#1453=ADVANCED_FACE('F956',(#1452),#1424,.F.);
#1454=CARTESIAN_POINT('',(38.63875,-1.75,3.09));
#1455=DIRECTION('',(1.,0.,0.));
#1456=DIRECTION('',(0.,1.,0.));
#1457=AXIS2_PLACEMENT_3D('',#1454,#1455,#1456);
#1458=CYLINDRICAL_SURFACE('',#1457,6.54);
#1459=ORIENTED_EDGE('',*,*,#732,.T.);
#1460=ORIENTED_EDGE('',*,*,#768,.T.);
#1461=ORIENTED_EDGE('',*,*,#689,.T.);
#1462=DIRECTION('',(-1.,0.,0.));
#1463=VECTOR('',#1462,1.);
#1464=CARTESIAN_POINT('',(40.,-8.2844566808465,3.35921345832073));
#1465=LINE('',#1464,#1463);
#1466=EDGE_CURVE('E635',#731,#679,#1465,.T.);
#1467=ORIENTED_EDGE('',*,*,#1466,.F.);
#1468=EDGE_LOOP('',(#1459,#1460,#1461,#1467));
#1469=FACE_BOUND('',#1468,.T.);
#1470=ADVANCED_FACE('F953',(#1469),#1458,.T.);
#1471=CARTESIAN_POINT('',(15.25,15.5,2.2));
#1472=DIRECTION('',(0.,0.,1.));
#1473=DIRECTION('',(-1.,0.,0.));
#1474=AXIS2_PLACEMENT_3D('',#1471,#1472,#1473);
#1475=PLANE('',#1474);
#1476=ORIENTED_EDGE('',*,*,#894,.T.);
#1477=ORIENTED_EDGE('',*,*,#911,.T.);
#1478=ORIENTED_EDGE('',*,*,#792,.T.);
#1479=ORIENTED_EDGE('',*,*,#821,.T.);
#1480=ORIENTED_EDGE('',*,*,#846,.T.);
#1481=ORIENTED_EDGE('',*,*,#870,.T.);
#1482=EDGE_LOOP('',(#1476,#1477,#1478,#1479,#1480,#1481));
#1483=FACE_BOUND('',#1482,.T.);
#1484=CARTESIAN_POINT('',(0.,0.,2.2));
#1485=DIRECTION('',(0.,0.,1.));
#1486=DIRECTION('',(-1.,0.,0.));
#1487=AXIS2_PLACEMENT_3D('',#1484,#1485,#1486);
#1488=CIRCLE('',#1487,3.25);
#1489=CARTESIAN_POINT('',(0.,3.25,2.2));
#1490=VERTEX_POINT('',#1489);
#1491=CARTESIAN_POINT('',(0.,-3.25,2.2));
#1492=VERTEX_POINT('',#1491);
#1493=EDGE_CURVE('E633',#1490,#1492,#1488,.F.);
#1494=ORIENTED_EDGE('',*,*,#1493,.T.);
#1495=CARTESIAN_POINT('',(0.,0.,2.2));
#1496=DIRECTION('',(0.,0.,1.));
#1497=DIRECTION('',(-1.,0.,0.));
#1498=AXIS2_PLACEMENT_3D('',#1495,#1496,#1497);
#1499=CIRCLE('',#1498,3.25);
#1500=EDGE_CURVE('E630',#1492,#1490,#1499,.F.);
#1501=ORIENTED_EDGE('',*,*,#1500,.T.);
#1502=EDGE_LOOP('',(#1494,#1501));
#1503=FACE_BOUND('',#1502,.T.);
#1504=ADVANCED_FACE('F826',(#1483,#1503),#1475,.T.);
#1505=CARTESIAN_POINT('',(15.25,15.5,2.2));
#1506=DIRECTION('',(0.,0.,1.));
#1507=DIRECTION('',(-1.,0.,0.));
#1508=AXIS2_PLACEMENT_3D('',#1505,#1506,#1507);
#1509=PLANE('',#1508);
#1510=ORIENTED_EDGE('',*,*,#1040,.T.);
#1511=ORIENTED_EDGE('',*,*,#1058,.T.);
#1512=ORIENTED_EDGE('',*,*,#938,.T.);
#1513=ORIENTED_EDGE('',*,*,#967,.T.);
#1514=ORIENTED_EDGE('',*,*,#992,.T.);
#1515=ORIENTED_EDGE('',*,*,#1016,.T.);
#1516=EDGE_LOOP('',(#1510,#1511,#1512,#1513,#1514,#1515));
#1517=FACE_BOUND('',#1516,.T.);
#1518=CARTESIAN_POINT('',(30.5,0.,2.2));
#1519=DIRECTION('',(0.,0.,1.));
#1520=DIRECTION('',(-1.,0.,0.));
#1521=AXIS2_PLACEMENT_3D('',#1518,#1519,#1520);
#1522=CIRCLE('',#1521,3.25);
#1523=CARTESIAN_POINT('',(30.5,3.25,2.2));
#1524=VERTEX_POINT('',#1523);
#1525=CARTESIAN_POINT('',(30.5,-3.25,2.2));
#1526=VERTEX_POINT('',#1525);
#1527=EDGE_CURVE('E627',#1524,#1526,#1522,.F.);
#1528=ORIENTED_EDGE('',*,*,#1527,.T.);
#1529=CARTESIAN_POINT('',(30.5,0.,2.2));
#1530=DIRECTION('',(0.,0.,1.));
#1531=DIRECTION('',(-1.,0.,0.));
#1532=AXIS2_PLACEMENT_3D('',#1529,#1530,#1531);
#1533=CIRCLE('',#1532,3.25);
#1534=EDGE_CURVE('E624',#1526,#1524,#1533,.F.);
#1535=ORIENTED_EDGE('',*,*,#1534,.T.);
#1536=EDGE_LOOP('',(#1528,#1535));
#1537=FACE_BOUND('',#1536,.T.);
#1538=ADVANCED_FACE('F946',(#1517,#1537),#1509,.T.);
#1539=CARTESIAN_POINT('',(40.,5.59267264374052,11.5));
#1540=DIRECTION('',(0.,-0.203476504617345,0.979079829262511));
#1541=DIRECTION('',(0.,0.979079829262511,0.203476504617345));
#1542=AXIS2_PLACEMENT_3D('',#1539,#1540,#1541);
#1543=PLANE('',#1542);
#1544=DIRECTION('',(0.,-0.979079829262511,-0.203476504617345));
#1545=VECTOR('',#1544,1.);
#1546=CARTESIAN_POINT('',(-9.5,5.59267264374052,11.5));
#1547=LINE('',#1546,#1545);
#1548=CARTESIAN_POINT('',(-9.5,5.59267264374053,11.5));
#1549=VERTEX_POINT('',#1548);
#1550=CARTESIAN_POINT('',(-9.5,-3.1214316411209,9.68899804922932));
#1551=VERTEX_POINT('',#1550);
#1552=EDGE_CURVE('E619',#1549,#1551,#1547,.T.);
#1553=ORIENTED_EDGE('',*,*,#1552,.T.);
#1554=DIRECTION('',(1.,0.,0.));
#1555=VECTOR('',#1554,1.);
#1556=CARTESIAN_POINT('',(40.,-3.1214316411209,9.68899804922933));
#1557=LINE('',#1556,#1555);
#1558=EDGE_CURVE('E667',#1084,#1551,#1557,.F.);
#1559=ORIENTED_EDGE('',*,*,#1558,.F.);
#1560=ORIENTED_EDGE('',*,*,#1085,.T.);
#1561=DIRECTION('',(1.,0.,0.));
#1562=VECTOR('',#1561,1.);
#1563=CARTESIAN_POINT('',(40.,5.59267264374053,11.5));
#1564=LINE('',#1563,#1562);
#1565=EDGE_CURVE('E666',#1549,#1076,#1564,.T.);
#1566=ORIENTED_EDGE('',*,*,#1565,.F.);
#1567=EDGE_LOOP('',(#1553,#1559,#1560,#1566));
#1568=FACE_BOUND('',#1567,.T.);
#1569=ADVANCED_FACE('F942',(#1568),#1543,.T.);
#1570=CARTESIAN_POINT('',(40.,-1.75,3.09));
#1571=DIRECTION('',(1.,0.,0.));
#1572=DIRECTION('',(0.,1.,0.));
#1573=AXIS2_PLACEMENT_3D('',#1570,#1571,#1572);
#1574=CYLINDRICAL_SURFACE('',#1573,6.74);
#1575=CARTESIAN_POINT('',(-9.5,-1.75,3.09));
#1576=DIRECTION('',(1.,0.,0.));
#1577=DIRECTION('',(0.,1.,0.));
#1578=AXIS2_PLACEMENT_3D('',#1575,#1576,#1577);
#1579=CIRCLE('',#1578,6.74);
#1580=CARTESIAN_POINT('',(-9.5,-8.4846213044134,3.35921345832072));
#1581=VERTEX_POINT('',#1580);
#1582=EDGE_CURVE('E616',#1551,#1581,#1579,.T.);
#1583=ORIENTED_EDGE('',*,*,#1582,.T.);
#1584=DIRECTION('',(-1.,0.,0.));
#1585=VECTOR('',#1584,1.);
#1586=CARTESIAN_POINT('',(40.,-8.4846213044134,3.35921345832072));
#1587=LINE('',#1586,#1585);
#1588=EDGE_CURVE('E1639',#1093,#1581,#1587,.T.);
#1589=ORIENTED_EDGE('',*,*,#1588,.F.);
#1590=ORIENTED_EDGE('',*,*,#1094,.T.);
#1591=ORIENTED_EDGE('',*,*,#1558,.T.);
#1592=EDGE_LOOP('',(#1583,#1589,#1590,#1591));
#1593=FACE_BOUND('',#1592,.T.);
#1594=ADVANCED_FACE('F938',(#1593),#1574,.T.);
#1595=CARTESIAN_POINT('',(40.,-8.87,-9.1));
#1596=DIRECTION('',(1.,0.,0.));
#1597=DIRECTION('',(0.,1.,0.));
#1598=AXIS2_PLACEMENT_3D('',#1595,#1596,#1597);
#1599=CYLINDRICAL_SURFACE('',#1598,25.17);
#1600=ORIENTED_EDGE('',*,*,#1565,.T.);
#1601=ORIENTED_EDGE('',*,*,#1321,.T.);
#1602=ORIENTED_EDGE('',*,*,#1134,.T.);
#1603=DIRECTION('',(-1.,0.,0.));
#1604=VECTOR('',#1603,1.);
#1605=CARTESIAN_POINT('',(40.,13.,3.35921345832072));
#1606=LINE('',#1605,#1604);
#1607=CARTESIAN_POINT('',(-9.5,13.,3.3592134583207));
#1608=VERTEX_POINT('',#1607);
#1609=EDGE_CURVE('E1625',#1608,#1126,#1606,.F.);
#1610=ORIENTED_EDGE('',*,*,#1609,.F.);
#1611=CARTESIAN_POINT('',(-9.5,-8.87,-9.1));
#1612=DIRECTION('',(1.,0.,0.));
#1613=DIRECTION('',(0.,1.,0.));
#1614=AXIS2_PLACEMENT_3D('',#1611,#1612,#1613);
#1615=CIRCLE('',#1614,25.17);
#1616=EDGE_CURVE('E620',#1608,#1549,#1615,.T.);
#1617=ORIENTED_EDGE('',*,*,#1616,.T.);
#1618=EDGE_LOOP('',(#1600,#1601,#1602,#1610,#1617));
#1619=FACE_BOUND('',#1618,.T.);
#1620=ADVANCED_FACE('F934',(#1619),#1599,.T.);
#1621=CARTESIAN_POINT('',(6.8,13.,3.35921345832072));
#1622=DIRECTION('',(0.,0.601465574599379,-0.798898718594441));
#1623=DIRECTION('',(0.,-0.798898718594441,-0.601465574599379));
#1624=AXIS2_PLACEMENT_3D('',#1621,#1622,#1623);
#1625=PLANE('',#1624);
#1626=ORIENTED_EDGE('',*,*,#1192,.T.);
#1627=DIRECTION('',(-1.,0.,0.));
#1628=VECTOR('',#1627,1.);
#1629=CARTESIAN_POINT('',(40.,13.,3.35921345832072));
#1630=LINE('',#1629,#1628);
#1631=EDGE_CURVE('E1622',#1126,#1185,#1630,.F.);
#1632=ORIENTED_EDGE('',*,*,#1631,.F.);
#1633=ORIENTED_EDGE('',*,*,#1127,.T.);
#1634=ORIENTED_EDGE('',*,*,#1161,.T.);
#1635=EDGE_LOOP('',(#1626,#1632,#1633,#1634));
#1636=FACE_BOUND('',#1635,.T.);
#1637=ADVANCED_FACE('F930',(#1636),#1625,.T.);
#1638=CARTESIAN_POINT('',(40.,-8.87,-9.1));
#1639=DIRECTION('',(1.,0.,0.));
#1640=DIRECTION('',(0.,1.,0.));
#1641=AXIS2_PLACEMENT_3D('',#1638,#1639,#1640);
#1642=CYLINDRICAL_SURFACE('',#1641,25.17);
#1643=ORIENTED_EDGE('',*,*,#1229,.T.);
#1644=DIRECTION('',(-1.,0.,0.));
#1645=VECTOR('',#1644,1.);
#1646=CARTESIAN_POINT('',(40.,13.,3.35921345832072));
#1647=LINE('',#1646,#1645);
#1648=EDGE_CURVE('E1615',#1185,#1221,#1647,.F.);
#1649=ORIENTED_EDGE('',*,*,#1648,.F.);
#1650=ORIENTED_EDGE('',*,*,#1186,.T.);
#1651=ORIENTED_EDGE('',*,*,#1314,.T.);
#1652=EDGE_LOOP('',(#1643,#1649,#1650,#1651));
#1653=FACE_BOUND('',#1652,.T.);
#1654=ADVANCED_FACE('F926',(#1653),#1642,.T.);
#1655=CARTESIAN_POINT('',(15.35,18.5073278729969,7.5055064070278));
#1656=DIRECTION('',(0.,0.601465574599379,-0.798898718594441));
#1657=DIRECTION('',(0.,-0.798898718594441,-0.601465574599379));
#1658=AXIS2_PLACEMENT_3D('',#1655,#1656,#1657);
#1659=PLANE('',#1658);
#1660=ORIENTED_EDGE('',*,*,#1222,.T.);
#1661=ORIENTED_EDGE('',*,*,#1254,.T.);
#1662=ORIENTED_EDGE('',*,*,#1279,.T.);
#1663=DIRECTION('',(-1.,0.,0.));
#1664=VECTOR('',#1663,1.);
#1665=CARTESIAN_POINT('',(40.,13.,3.35921345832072));
#1666=LINE('',#1665,#1664);
#1667=EDGE_CURVE('E1612',#1221,#1272,#1666,.F.);
#1668=ORIENTED_EDGE('',*,*,#1667,.F.);
#1669=EDGE_LOOP('',(#1660,#1661,#1662,#1668));
#1670=FACE_BOUND('',#1669,.T.);
#1671=ADVANCED_FACE('F922',(#1670),#1659,.T.);
#1672=CARTESIAN_POINT('',(40.,-8.87,-9.1));
#1673=DIRECTION('',(1.,0.,0.));
#1674=DIRECTION('',(0.,1.,0.));
#1675=AXIS2_PLACEMENT_3D('',#1672,#1673,#1674);
#1676=CYLINDRICAL_SURFACE('',#1675,25.17);
#1677=ORIENTED_EDGE('',*,*,#1273,.T.);
#1678=ORIENTED_EDGE('',*,*,#1307,.T.);
#1679=ORIENTED_EDGE('',*,*,#1361,.T.);
#1680=DIRECTION('',(-1.,0.,0.));
#1681=VECTOR('',#1680,1.);
#1682=CARTESIAN_POINT('',(40.,13.,3.35921345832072));
#1683=LINE('',#1682,#1681);
#1684=EDGE_CURVE('E1605',#1272,#1353,#1683,.F.);
#1685=ORIENTED_EDGE('',*,*,#1684,.F.);
#1686=EDGE_LOOP('',(#1677,#1678,#1679,#1685));
#1687=FACE_BOUND('',#1686,.T.);
#1688=ADVANCED_FACE('F918',(#1687),#1676,.T.);
#1689=CARTESIAN_POINT('',(32.05,18.5073278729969,7.5055064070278));
#1690=DIRECTION('',(0.,0.601465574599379,-0.798898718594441));
#1691=DIRECTION('',(0.,-0.798898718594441,-0.601465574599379));
#1692=AXIS2_PLACEMENT_3D('',#1689,#1690,#1691);
#1693=PLANE('',#1692);
#1694=ORIENTED_EDGE('',*,*,#1354,.T.);
#1695=ORIENTED_EDGE('',*,*,#1386,.T.);
#1696=ORIENTED_EDGE('',*,*,#1411,.T.);
#1697=DIRECTION('',(-1.,0.,0.));
#1698=VECTOR('',#1697,1.);
#1699=CARTESIAN_POINT('',(40.,13.,3.35921345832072));
#1700=LINE('',#1699,#1698);
#1701=EDGE_CURVE('E1594',#1353,#1404,#1700,.F.);
#1702=ORIENTED_EDGE('',*,*,#1701,.F.);
#1703=EDGE_LOOP('',(#1694,#1695,#1696,#1702));
#1704=FACE_BOUND('',#1703,.T.);
#1705=ADVANCED_FACE('F914',(#1704),#1693,.T.);
#1706=CARTESIAN_POINT('',(40.,-8.87,-9.1));
#1707=DIRECTION('',(1.,0.,0.));
#1708=DIRECTION('',(0.,1.,0.));
#1709=AXIS2_PLACEMENT_3D('',#1706,#1707,#1708);
#1710=CYLINDRICAL_SURFACE('',#1709,25.17);
#1711=CARTESIAN_POINT('',(40.,-8.87,-9.1));
#1712=DIRECTION('',(1.,0.,0.));
#1713=DIRECTION('',(0.,1.,0.));
#1714=AXIS2_PLACEMENT_3D('',#1711,#1712,#1713);
#1715=CIRCLE('',#1714,25.17);
#1716=CARTESIAN_POINT('',(40.,13.,3.3592134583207));
#1717=VERTEX_POINT('',#1716);
#1718=CARTESIAN_POINT('',(40.,5.59267264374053,11.5));
#1719=VERTEX_POINT('',#1718);
#1720=EDGE_CURVE('E612',#1717,#1719,#1715,.T.);
#1721=ORIENTED_EDGE('',*,*,#1720,.F.);
#1722=DIRECTION('',(-1.,0.,0.));
#1723=VECTOR('',#1722,1.);
#1724=CARTESIAN_POINT('',(40.,13.,3.35921345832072));
#1725=LINE('',#1724,#1723);
#1726=EDGE_CURVE('E1592',#1404,#1717,#1725,.F.);
#1727=ORIENTED_EDGE('',*,*,#1726,.F.);
#1728=ORIENTED_EDGE('',*,*,#1405,.T.);
#1729=DIRECTION('',(-1.,0.,0.));
#1730=VECTOR('',#1729,1.);
#1731=CARTESIAN_POINT('',(40.,5.59267264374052,11.5));
#1732=LINE('',#1731,#1730);
#1733=EDGE_CURVE('E640',#1719,#568,#1732,.T.);
#1734=ORIENTED_EDGE('',*,*,#1733,.F.);
#1735=EDGE_LOOP('',(#1721,#1727,#1728,#1734));
#1736=FACE_BOUND('',#1735,.T.);
#1737=ADVANCED_FACE('F910',(#1736),#1710,.T.);
#1738=CARTESIAN_POINT('',(40.,5.59267264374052,11.5));
#1739=DIRECTION('',(0.,-0.203476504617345,0.979079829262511));
#1740=DIRECTION('',(0.,0.979079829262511,0.203476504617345));
#1741=AXIS2_PLACEMENT_3D('',#1738,#1739,#1740);
#1742=PLANE('',#1741);
#1743=ORIENTED_EDGE('',*,*,#1733,.T.);
#1744=ORIENTED_EDGE('',*,*,#569,.F.);
#1745=ORIENTED_EDGE('',*,*,#1449,.T.);
#1746=DIRECTION('',(1.,0.,0.));
#1747=VECTOR('',#1746,1.);
#1748=CARTESIAN_POINT('',(40.,-3.1214316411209,9.68899804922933));
#1749=LINE('',#1748,#1747);
#1750=CARTESIAN_POINT('',(40.,-3.1214316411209,9.68899804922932));
#1751=VERTEX_POINT('',#1750);
#1752=EDGE_CURVE('E639',#1751,#1442,#1749,.F.);
#1753=ORIENTED_EDGE('',*,*,#1752,.F.);
#1754=DIRECTION('',(0.,-0.979079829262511,-0.203476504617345));
#1755=VECTOR('',#1754,1.);
#1756=CARTESIAN_POINT('',(40.,5.59267264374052,11.5));
#1757=LINE('',#1756,#1755);
#1758=EDGE_CURVE('E611',#1719,#1751,#1757,.T.);
#1759=ORIENTED_EDGE('',*,*,#1758,.F.);
#1760=EDGE_LOOP('',(#1743,#1744,#1745,#1753,#1759));
#1761=FACE_BOUND('',#1760,.T.);
#1762=ADVANCED_FACE('F906',(#1761),#1742,.T.);
#1763=CARTESIAN_POINT('',(40.,-1.75,3.09));
#1764=DIRECTION('',(1.,0.,0.));
#1765=DIRECTION('',(0.,1.,0.));
#1766=AXIS2_PLACEMENT_3D('',#1763,#1764,#1765);
#1767=CYLINDRICAL_SURFACE('',#1766,6.74);
#1768=CARTESIAN_POINT('',(40.,-1.75,3.09));
#1769=DIRECTION('',(1.,0.,0.));
#1770=DIRECTION('',(0.,1.,0.));
#1771=AXIS2_PLACEMENT_3D('',#1768,#1769,#1770);
#1772=CIRCLE('',#1771,6.74);
#1773=CARTESIAN_POINT('',(40.,-8.4846213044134,3.35921345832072));
#1774=VERTEX_POINT('',#1773);
#1775=EDGE_CURVE('E607',#1751,#1774,#1772,.T.);
#1776=ORIENTED_EDGE('',*,*,#1775,.F.);
#1777=ORIENTED_EDGE('',*,*,#1752,.T.);
#1778=ORIENTED_EDGE('',*,*,#1443,.T.);
#1779=DIRECTION('',(-1.,0.,0.));
#1780=VECTOR('',#1779,1.);
#1781=CARTESIAN_POINT('',(40.,-8.4846213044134,3.35921345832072));
#1782=LINE('',#1781,#1780);
#1783=EDGE_CURVE('E758',#1774,#1433,#1782,.T.);
#1784=ORIENTED_EDGE('',*,*,#1783,.F.);
#1785=EDGE_LOOP('',(#1776,#1777,#1778,#1784));
#1786=FACE_BOUND('',#1785,.T.);
#1787=ADVANCED_FACE('F903',(#1786),#1767,.T.);
#1788=CARTESIAN_POINT('',(40.,-8.4846213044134,3.35921345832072));
#1789=DIRECTION('',(0.,0.,1.));
#1790=DIRECTION('',(0.,1.,0.));
#1791=AXIS2_PLACEMENT_3D('',#1788,#1789,#1790);
#1792=PLANE('',#1791);
#1793=ORIENTED_EDGE('',*,*,#738,.F.);
#1794=ORIENTED_EDGE('',*,*,#1466,.T.);
#1795=ORIENTED_EDGE('',*,*,#680,.T.);
#1796=ORIENTED_EDGE('',*,*,#219,.F.);
#1797=ORIENTED_EDGE('',*,*,#1100,.F.);
#1798=ORIENTED_EDGE('',*,*,#1588,.T.);
#1799=DIRECTION('',(0.,1.,0.));
#1800=VECTOR('',#1799,1.);
#1801=CARTESIAN_POINT('',(-9.5,15.5,3.35921345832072));
#1802=LINE('',#1801,#1800);
#1803=CARTESIAN_POINT('',(-9.5,-8.5,3.35921345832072));
#1804=VERTEX_POINT('',#1803);
#1805=EDGE_CURVE('E618',#1581,#1804,#1802,.F.);
#1806=ORIENTED_EDGE('',*,*,#1805,.T.);
#1807=DIRECTION('',(1.,0.,0.));
#1808=VECTOR('',#1807,1.);
#1809=CARTESIAN_POINT('',(40.,-8.5,3.35921345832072));
#1810=LINE('',#1809,#1808);
#1811=CARTESIAN_POINT('',(40.,-8.5,3.35921345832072));
#1812=VERTEX_POINT('',#1811);
#1813=EDGE_CURVE('E606',#1812,#1804,#1810,.F.);
#1814=ORIENTED_EDGE('',*,*,#1813,.F.);
#1815=DIRECTION('',(0.,1.,0.));
#1816=VECTOR('',#1815,1.);
#1817=CARTESIAN_POINT('',(40.,15.5,3.35921345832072));
#1818=LINE('',#1817,#1816);
#1819=EDGE_CURVE('E610',#1774,#1812,#1818,.F.);
#1820=ORIENTED_EDGE('',*,*,#1819,.F.);
#1821=ORIENTED_EDGE('',*,*,#1783,.T.);
#1822=ORIENTED_EDGE('',*,*,#1434,.T.);
#1823=ORIENTED_EDGE('',*,*,#633,.F.);
#1824=EDGE_LOOP('',(#1793,#1794,#1795,#1796,#1797,#1798,#1806,#1814,#1820,#1821,#1822,#1823));
#1825=FACE_BOUND('',#1824,.T.);
#1826=ADVANCED_FACE('F899',(#1825),#1792,.T.);
#1827=CARTESIAN_POINT('',(0.,0.,2.2));
#1828=DIRECTION('',(0.,0.,1.));
#1829=DIRECTION('',(-1.,0.,0.));
#1830=AXIS2_PLACEMENT_3D('',#1827,#1828,#1829);
#1831=CYLINDRICAL_SURFACE('',#1830,3.25);
#1832=CARTESIAN_POINT('',(0.,0.,0.));
#1833=DIRECTION('',(0.,0.,1.));
#1834=DIRECTION('',(-1.,0.,0.));
#1835=AXIS2_PLACEMENT_3D('',#1832,#1833,#1834);
#1836=CIRCLE('',#1835,3.25);
#1837=CARTESIAN_POINT('',(0.,-3.25,0.));
#1838=VERTEX_POINT('',#1837);
#1839=CARTESIAN_POINT('',(0.,3.25,0.));
#1840=VERTEX_POINT('',#1839);
#1841=EDGE_CURVE('E603',#1838,#1840,#1836,.T.);
#1842=ORIENTED_EDGE('',*,*,#1841,.F.);
#1843=DIRECTION('',(0.,0.,1.));
#1844=VECTOR('',#1843,1.);
#1845=CARTESIAN_POINT('',(0.,-3.25,2.2));
#1846=LINE('',#1845,#1844);
#1847=EDGE_CURVE('E632',#1838,#1492,#1846,.T.);
#1848=ORIENTED_EDGE('',*,*,#1847,.T.);
#1849=ORIENTED_EDGE('',*,*,#1493,.F.);
#1850=DIRECTION('',(0.,0.,1.));
#1851=VECTOR('',#1850,1.);
#1852=CARTESIAN_POINT('',(0.,3.25,2.2));
#1853=LINE('',#1852,#1851);
#1854=EDGE_CURVE('E629',#1490,#1840,#1853,.F.);
#1855=ORIENTED_EDGE('',*,*,#1854,.T.);
#1856=EDGE_LOOP('',(#1842,#1848,#1849,#1855));
#1857=FACE_BOUND('',#1856,.T.);
#1858=ADVANCED_FACE('F895',(#1857),#1831,.F.);
#1859=CARTESIAN_POINT('',(0.,0.,2.2));
#1860=DIRECTION('',(0.,0.,1.));
#1861=DIRECTION('',(-1.,0.,0.));
#1862=AXIS2_PLACEMENT_3D('',#1859,#1860,#1861);
#1863=CYLINDRICAL_SURFACE('',#1862,3.25);
#1864=ORIENTED_EDGE('',*,*,#1500,.F.);
#1865=ORIENTED_EDGE('',*,*,#1847,.F.);
#1866=CARTESIAN_POINT('',(0.,0.,0.));
#1867=DIRECTION('',(0.,0.,1.));
#1868=DIRECTION('',(-1.,0.,0.));
#1869=AXIS2_PLACEMENT_3D('',#1866,#1867,#1868);
#1870=CIRCLE('',#1869,3.25);
#1871=EDGE_CURVE('E600',#1840,#1838,#1870,.T.);
#1872=ORIENTED_EDGE('',*,*,#1871,.F.);
#1873=ORIENTED_EDGE('',*,*,#1854,.F.);
#1874=EDGE_LOOP('',(#1864,#1865,#1872,#1873));
#1875=FACE_BOUND('',#1874,.T.);
#1876=ADVANCED_FACE('F891',(#1875),#1863,.F.);
#1877=CARTESIAN_POINT('',(30.5,0.,2.2));
#1878=DIRECTION('',(0.,0.,1.));
#1879=DIRECTION('',(-1.,0.,0.));
#1880=AXIS2_PLACEMENT_3D('',#1877,#1878,#1879);
#1881=CYLINDRICAL_SURFACE('',#1880,3.25);
#1882=CARTESIAN_POINT('',(30.5,0.,0.));
#1883=DIRECTION('',(0.,0.,1.));
#1884=DIRECTION('',(-1.,0.,0.));
#1885=AXIS2_PLACEMENT_3D('',#1882,#1883,#1884);
#1886=CIRCLE('',#1885,3.25);
#1887=CARTESIAN_POINT('',(30.5,-3.25,0.));
#1888=VERTEX_POINT('',#1887);
#1889=CARTESIAN_POINT('',(30.5,3.25,0.));
#1890=VERTEX_POINT('',#1889);
#1891=EDGE_CURVE('E597',#1888,#1890,#1886,.T.);
#1892=ORIENTED_EDGE('',*,*,#1891,.F.);
#1893=DIRECTION('',(0.,0.,1.));
#1894=VECTOR('',#1893,1.);
#1895=CARTESIAN_POINT('',(30.5,-3.25,2.2));
#1896=LINE('',#1895,#1894);
#1897=EDGE_CURVE('E626',#1888,#1526,#1896,.T.);
#1898=ORIENTED_EDGE('',*,*,#1897,.T.);
#1899=ORIENTED_EDGE('',*,*,#1527,.F.);
#1900=DIRECTION('',(0.,0.,1.));
#1901=VECTOR('',#1900,1.);
#1902=CARTESIAN_POINT('',(30.5,3.25,2.2));
#1903=LINE('',#1902,#1901);
#1904=EDGE_CURVE('E623',#1524,#1890,#1903,.F.);
#1905=ORIENTED_EDGE('',*,*,#1904,.T.);
#1906=EDGE_LOOP('',(#1892,#1898,#1899,#1905));
#1907=FACE_BOUND('',#1906,.T.);
#1908=ADVANCED_FACE('F887',(#1907),#1881,.F.);
#1909=CARTESIAN_POINT('',(30.5,0.,2.2));
#1910=DIRECTION('',(0.,0.,1.));
#1911=DIRECTION('',(-1.,0.,0.));
#1912=AXIS2_PLACEMENT_3D('',#1909,#1910,#1911);
#1913=CYLINDRICAL_SURFACE('',#1912,3.25);
#1914=ORIENTED_EDGE('',*,*,#1534,.F.);
#1915=ORIENTED_EDGE('',*,*,#1897,.F.);
#1916=CARTESIAN_POINT('',(30.5,0.,0.));
#1917=DIRECTION('',(0.,0.,1.));
#1918=DIRECTION('',(-1.,0.,0.));
#1919=AXIS2_PLACEMENT_3D('',#1916,#1917,#1918);
#1920=CIRCLE('',#1919,3.25);
#1921=EDGE_CURVE('E593',#1890,#1888,#1920,.T.);
#1922=ORIENTED_EDGE('',*,*,#1921,.F.);
#1923=ORIENTED_EDGE('',*,*,#1904,.F.);
#1924=EDGE_LOOP('',(#1914,#1915,#1922,#1923));
#1925=FACE_BOUND('',#1924,.T.);
#1926=ADVANCED_FACE('F883',(#1925),#1913,.F.);
#1927=CARTESIAN_POINT('',(-9.5,15.5,0.));
#1928=DIRECTION('',(1.,0.,0.));
#1929=DIRECTION('',(0.,1.,0.));
#1930=AXIS2_PLACEMENT_3D('',#1927,#1928,#1929);
#1931=PLANE('',#1930);
#1932=DIRECTION('',(0.,-1.,0.));
#1933=VECTOR('',#1932,1.);
#1934=CARTESIAN_POINT('',(-9.5,-8.5,0.));
#1935=LINE('',#1934,#1933);
#1936=CARTESIAN_POINT('',(-9.5,-8.5,0.));
#1937=VERTEX_POINT('',#1936);
#1938=CARTESIAN_POINT('',(-9.5,13.,0.));
#1939=VERTEX_POINT('',#1938);
#1940=EDGE_CURVE('E596',#1937,#1939,#1935,.F.);
#1941=ORIENTED_EDGE('',*,*,#1940,.F.);
#1942=DIRECTION('',(0.,0.,1.));
#1943=VECTOR('',#1942,1.);
#1944=CARTESIAN_POINT('',(-9.5,-8.5,3.35921345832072));
#1945=LINE('',#1944,#1943);
#1946=EDGE_CURVE('E1642',#1804,#1937,#1945,.F.);
#1947=ORIENTED_EDGE('',*,*,#1946,.F.);
#1948=ORIENTED_EDGE('',*,*,#1805,.F.);
#1949=ORIENTED_EDGE('',*,*,#1582,.F.);
#1950=ORIENTED_EDGE('',*,*,#1552,.F.);
#1951=ORIENTED_EDGE('',*,*,#1616,.F.);
#1952=DIRECTION('',(0.,0.,1.));
#1953=VECTOR('',#1952,1.);
#1954=CARTESIAN_POINT('',(-9.5,13.,0.));
#1955=LINE('',#1954,#1953);
#1956=EDGE_CURVE('E1630',#1939,#1608,#1955,.T.);
#1957=ORIENTED_EDGE('',*,*,#1956,.F.);
#1958=EDGE_LOOP('',(#1941,#1947,#1948,#1949,#1950,#1951,#1957));
#1959=FACE_BOUND('',#1958,.T.);
#1960=ADVANCED_FACE('F879',(#1959),#1931,.F.);
#1961=CARTESIAN_POINT('',(40.,13.,0.));
#1962=DIRECTION('',(0.,1.,0.));
#1963=DIRECTION('',(-1.,0.,0.));
#1964=AXIS2_PLACEMENT_3D('',#1961,#1962,#1963);
#1965=PLANE('',#1964);
#1966=DIRECTION('',(0.,0.,1.));
#1967=VECTOR('',#1966,1.);
#1968=CARTESIAN_POINT('',(40.,13.,0.));
#1969=LINE('',#1968,#1967);
#1970=CARTESIAN_POINT('',(40.,13.,0.));
#1971=VERTEX_POINT('',#1970);
#1972=EDGE_CURVE('E615',#1971,#1717,#1969,.T.);
#1973=ORIENTED_EDGE('',*,*,#1972,.F.);
#1974=DIRECTION('',(1.,0.,0.));
#1975=VECTOR('',#1974,1.);
#1976=CARTESIAN_POINT('',(40.,13.,0.));
#1977=LINE('',#1976,#1975);
#1978=EDGE_CURVE('E1596',#1939,#1971,#1977,.T.);
#1979=ORIENTED_EDGE('',*,*,#1978,.F.);
#1980=ORIENTED_EDGE('',*,*,#1956,.T.);
#1981=ORIENTED_EDGE('',*,*,#1609,.T.);
#1982=ORIENTED_EDGE('',*,*,#1631,.T.);
#1983=ORIENTED_EDGE('',*,*,#1648,.T.);
#1984=ORIENTED_EDGE('',*,*,#1667,.T.);
#1985=ORIENTED_EDGE('',*,*,#1684,.T.);
#1986=ORIENTED_EDGE('',*,*,#1701,.T.);
#1987=ORIENTED_EDGE('',*,*,#1726,.T.);
#1988=EDGE_LOOP('',(#1973,#1979,#1980,#1981,#1982,#1983,#1984,#1985,#1986,#1987));
#1989=FACE_BOUND('',#1988,.T.);
#1990=ADVANCED_FACE('F876',(#1989),#1965,.T.);
#1991=CARTESIAN_POINT('',(40.,15.5,0.));
#1992=DIRECTION('',(1.,0.,0.));
#1993=DIRECTION('',(0.,1.,0.));
#1994=AXIS2_PLACEMENT_3D('',#1991,#1992,#1993);
#1995=PLANE('',#1994);
#1996=ORIENTED_EDGE('',*,*,#1819,.T.);
#1997=DIRECTION('',(0.,0.,1.));
#1998=VECTOR('',#1997,1.);
#1999=CARTESIAN_POINT('',(40.,-8.5,3.35921345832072));
#2000=LINE('',#1999,#1998);
#2001=CARTESIAN_POINT('',(40.,-8.5,0.));
#2002=VERTEX_POINT('',#2001);
#2003=EDGE_CURVE('E32',#2002,#1812,#2000,.T.);
#2004=ORIENTED_EDGE('',*,*,#2003,.F.);
#2005=DIRECTION('',(0.,-1.,0.));
#2006=VECTOR('',#2005,1.);
#2007=CARTESIAN_POINT('',(40.,-8.5,0.));
#2008=LINE('',#2007,#2006);
#2009=EDGE_CURVE('E23',#1971,#2002,#2008,.T.);
#2010=ORIENTED_EDGE('',*,*,#2009,.F.);
#2011=ORIENTED_EDGE('',*,*,#1972,.T.);
#2012=ORIENTED_EDGE('',*,*,#1720,.T.);
#2013=ORIENTED_EDGE('',*,*,#1758,.T.);
#2014=ORIENTED_EDGE('',*,*,#1775,.T.);
#2015=EDGE_LOOP('',(#1996,#2004,#2010,#2011,#2012,#2013,#2014));
#2016=FACE_BOUND('',#2015,.T.);
#2017=ADVANCED_FACE('F868',(#2016),#1995,.T.);
#2018=CARTESIAN_POINT('',(40.,-8.5,3.35921345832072));
#2019=DIRECTION('',(0.,-1.,0.));
#2020=DIRECTION('',(1.,0.,0.));
#2021=AXIS2_PLACEMENT_3D('',#2018,#2019,#2020);
#2022=PLANE('',#2021);
#2023=ORIENTED_EDGE('',*,*,#2003,.T.);
#2024=ORIENTED_EDGE('',*,*,#1813,.T.);
#2025=ORIENTED_EDGE('',*,*,#1946,.T.);
#2026=DIRECTION('',(1.,0.,0.));
#2027=VECTOR('',#2026,1.);
#2028=CARTESIAN_POINT('',(40.,-8.5,0.));
#2029=LINE('',#2028,#2027);
#2030=EDGE_CURVE('E9',#2002,#1937,#2029,.F.);
#2031=ORIENTED_EDGE('',*,*,#2030,.F.);
#2032=EDGE_LOOP('',(#2023,#2024,#2025,#2031));
#2033=FACE_BOUND('',#2032,.T.);
#2034=ADVANCED_FACE('F861',(#2033),#2022,.T.);
#2035=CARTESIAN_POINT('',(40.,-8.5,0.));
#2036=DIRECTION('',(0.,0.,-1.));
#2037=DIRECTION('',(1.,0.,0.));
#2038=AXIS2_PLACEMENT_3D('',#2035,#2036,#2037);
#2039=PLANE('',#2038);
#2040=ORIENTED_EDGE('',*,*,#2009,.T.);
#2041=ORIENTED_EDGE('',*,*,#2030,.T.);
#2042=ORIENTED_EDGE('',*,*,#1940,.T.);
#2043=ORIENTED_EDGE('',*,*,#1978,.T.);
#2044=EDGE_LOOP('',(#2040,#2041,#2042,#2043));
#2045=FACE_BOUND('',#2044,.T.);
#2046=ORIENTED_EDGE('',*,*,#1891,.T.);
#2047=ORIENTED_EDGE('',*,*,#1921,.T.);
#2048=EDGE_LOOP('',(#2046,#2047));
#2049=FACE_BOUND('',#2048,.T.);
#2050=ORIENTED_EDGE('',*,*,#1841,.T.);
#2051=ORIENTED_EDGE('',*,*,#1871,.T.);
#2052=EDGE_LOOP('',(#2050,#2051));
#2053=FACE_BOUND('',#2052,.T.);
#2054=ADVANCED_FACE('F859',(#2045,#2049,#2053),#2039,.T.);
#2055=CLOSED_SHELL('',(#74,#107,#149,#196,#238,#269,#311,#335,#377,#401,#441,#481,#523,#547,
#595,#637,#668,#709,#750,#772,#803,#828,#852,#876,#900,#918,#949,#974,#998,#1022,#1046,#1064,
#1105,#1142,#1167,#1196,#1233,#1258,#1287,#1328,#1365,#1390,#1419,#1453,#1470,#1504,#1538,#1569,
#1594,#1620,#1637,#1654,#1671,#1688,#1705,#1737,#1762,#1787,#1826,#1858,#1876,#1908,#1926,#1960,
#1990,#2017,#2034,#2054));
#2056=MANIFOLD_SOLID_BREP('B1',#2055);
#2057=ADVANCED_BREP_SHAPE_REPRESENTATION('',(#18,#2056),#14);
#2058=SHAPE_DEFINITION_REPRESENTATION(#9,#2057);
ENDSEC;
END-ISO-10303-21;
